VERSION 5.8 ;
BUSBITCHARS "[]" ;
DIVIDERCHAR "/" ;
UNITS
    DATABASE MICRONS 1000 ;
END UNITS

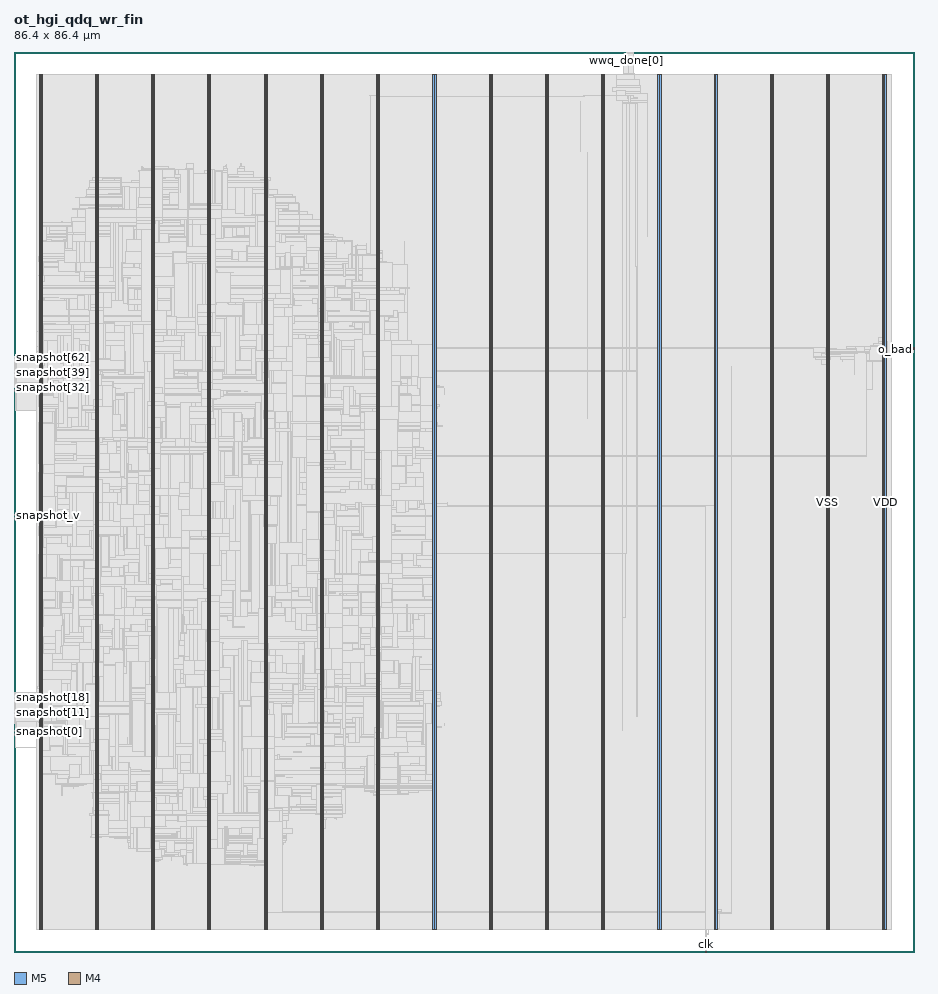
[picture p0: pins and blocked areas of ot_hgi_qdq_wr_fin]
MACRO ot_hgi_qdq_wr_fin
  FOREIGN ot_hgi_qdq_wr_fin 0 0 ;
  CLASS BLOCK ;
  SIZE 86.4 BY 86.4 ;
  PIN clk
    DIRECTION INPUT ;
    USE SIGNAL ;
    PORT
      LAYER M5 ;
        RECT  66.384 0 66.408 0.084 ;
    END
  END clk
  PIN o_bad
    DIRECTION OUTPUT ;
    USE SIGNAL ;
    PORT
      LAYER M4 ;
        RECT  86.316 57.84 86.4 57.864 ;
    END
  END o_bad
  PIN o_fin
    DIRECTION OUTPUT ;
    USE SIGNAL ;
    PORT
      LAYER M4 ;
        RECT  86.316 57.936 86.4 57.96 ;
    END
  END o_fin
  PIN o_idle
    DIRECTION OUTPUT ;
    USE SIGNAL ;
    PORT
      LAYER M4 ;
        RECT  86.316 58.032 86.4 58.056 ;
    END
  END o_idle
  PIN rst_n
    DIRECTION INPUT ;
    USE SIGNAL ;
    PORT
      LAYER M5 ;
        RECT  66.48 0 66.504 0.084 ;
    END
  END rst_n
  PIN snapshot[0]
    DIRECTION INPUT ;
    USE SIGNAL ;
    PORT
      LAYER M4 ;
        RECT  0 21.936 0.084 21.96 ;
    END
  END snapshot[0]
  PIN snapshot[10]
    DIRECTION INPUT ;
    USE SIGNAL ;
    PORT
      LAYER M4 ;
        RECT  0 22.896 0.084 22.92 ;
    END
  END snapshot[10]
  PIN snapshot[11]
    DIRECTION INPUT ;
    USE SIGNAL ;
    PORT
      LAYER M4 ;
        RECT  0 22.992 0.084 23.016 ;
    END
  END snapshot[11]
  PIN snapshot[12]
    DIRECTION INPUT ;
    USE SIGNAL ;
    PORT
      LAYER M4 ;
        RECT  0 23.088 0.084 23.112 ;
    END
  END snapshot[12]
  PIN snapshot[13]
    DIRECTION INPUT ;
    USE SIGNAL ;
    PORT
      LAYER M4 ;
        RECT  0 23.184 0.084 23.208 ;
    END
  END snapshot[13]
  PIN snapshot[14]
    DIRECTION INPUT ;
    USE SIGNAL ;
    PORT
      LAYER M4 ;
        RECT  0 23.28 0.084 23.304 ;
    END
  END snapshot[14]
  PIN snapshot[15]
    DIRECTION INPUT ;
    USE SIGNAL ;
    PORT
      LAYER M4 ;
        RECT  0 23.376 0.084 23.4 ;
    END
  END snapshot[15]
  PIN snapshot[16]
    DIRECTION INPUT ;
    USE SIGNAL ;
    PORT
      LAYER M4 ;
        RECT  0 23.472 0.084 23.496 ;
    END
  END snapshot[16]
  PIN snapshot[17]
    DIRECTION INPUT ;
    USE SIGNAL ;
    PORT
      LAYER M4 ;
        RECT  0 23.568 0.084 23.592 ;
    END
  END snapshot[17]
  PIN snapshot[18]
    DIRECTION INPUT ;
    USE SIGNAL ;
    PORT
      LAYER M4 ;
        RECT  0 23.664 0.084 23.688 ;
    END
  END snapshot[18]
  PIN snapshot[19]
    DIRECTION INPUT ;
    USE SIGNAL ;
    PORT
      LAYER M4 ;
        RECT  0 23.76 0.084 23.784 ;
    END
  END snapshot[19]
  PIN snapshot[1]
    DIRECTION INPUT ;
    USE SIGNAL ;
    PORT
      LAYER M4 ;
        RECT  0 22.032 0.084 22.056 ;
    END
  END snapshot[1]
  PIN snapshot[20]
    DIRECTION INPUT ;
    USE SIGNAL ;
    PORT
      LAYER M4 ;
        RECT  0 23.856 0.084 23.88 ;
    END
  END snapshot[20]
  PIN snapshot[21]
    DIRECTION INPUT ;
    USE SIGNAL ;
    PORT
      LAYER M4 ;
        RECT  0 23.952 0.084 23.976 ;
    END
  END snapshot[21]
  PIN snapshot[22]
    DIRECTION INPUT ;
    USE SIGNAL ;
    PORT
      LAYER M4 ;
        RECT  0 24.048 0.084 24.072 ;
    END
  END snapshot[22]
  PIN snapshot[23]
    DIRECTION INPUT ;
    USE SIGNAL ;
    PORT
      LAYER M4 ;
        RECT  0 24.144 0.084 24.168 ;
    END
  END snapshot[23]
  PIN snapshot[24]
    DIRECTION INPUT ;
    USE SIGNAL ;
    PORT
      LAYER M4 ;
        RECT  0 24.24 0.084 24.264 ;
    END
  END snapshot[24]
  PIN snapshot[25]
    DIRECTION INPUT ;
    USE SIGNAL ;
    PORT
      LAYER M4 ;
        RECT  0 24.336 0.084 24.36 ;
    END
  END snapshot[25]
  PIN snapshot[26]
    DIRECTION INPUT ;
    USE SIGNAL ;
    PORT
      LAYER M4 ;
        RECT  0 24.432 0.084 24.456 ;
    END
  END snapshot[26]
  PIN snapshot[27]
    DIRECTION INPUT ;
    USE SIGNAL ;
    PORT
      LAYER M4 ;
        RECT  0 24.528 0.084 24.552 ;
    END
  END snapshot[27]
  PIN snapshot[28]
    DIRECTION INPUT ;
    USE SIGNAL ;
    PORT
      LAYER M4 ;
        RECT  0 24.624 0.084 24.648 ;
    END
  END snapshot[28]
  PIN snapshot[29]
    DIRECTION INPUT ;
    USE SIGNAL ;
    PORT
      LAYER M4 ;
        RECT  0 24.72 0.084 24.744 ;
    END
  END snapshot[29]
  PIN snapshot[2]
    DIRECTION INPUT ;
    USE SIGNAL ;
    PORT
      LAYER M4 ;
        RECT  0 22.128 0.084 22.152 ;
    END
  END snapshot[2]
  PIN snapshot[30]
    DIRECTION INPUT ;
    USE SIGNAL ;
    PORT
      LAYER M4 ;
        RECT  0 24.816 0.084 24.84 ;
    END
  END snapshot[30]
  PIN snapshot[31]
    DIRECTION INPUT ;
    USE SIGNAL ;
    PORT
      LAYER M4 ;
        RECT  0 24.912 0.084 24.936 ;
    END
  END snapshot[31]
  PIN snapshot[32]
    DIRECTION INPUT ;
    USE SIGNAL ;
    PORT
      LAYER M4 ;
        RECT  0 54.192 0.084 54.216 ;
    END
  END snapshot[32]
  PIN snapshot[33]
    DIRECTION INPUT ;
    USE SIGNAL ;
    PORT
      LAYER M4 ;
        RECT  0 54.288 0.084 54.312 ;
    END
  END snapshot[33]
  PIN snapshot[34]
    DIRECTION INPUT ;
    USE SIGNAL ;
    PORT
      LAYER M4 ;
        RECT  0 54.384 0.084 54.408 ;
    END
  END snapshot[34]
  PIN snapshot[35]
    DIRECTION INPUT ;
    USE SIGNAL ;
    PORT
      LAYER M4 ;
        RECT  0 54.48 0.084 54.504 ;
    END
  END snapshot[35]
  PIN snapshot[36]
    DIRECTION INPUT ;
    USE SIGNAL ;
    PORT
      LAYER M4 ;
        RECT  0 54.576 0.084 54.6 ;
    END
  END snapshot[36]
  PIN snapshot[37]
    DIRECTION INPUT ;
    USE SIGNAL ;
    PORT
      LAYER M4 ;
        RECT  0 54.672 0.084 54.696 ;
    END
  END snapshot[37]
  PIN snapshot[38]
    DIRECTION INPUT ;
    USE SIGNAL ;
    PORT
      LAYER M4 ;
        RECT  0 54.768 0.084 54.792 ;
    END
  END snapshot[38]
  PIN snapshot[39]
    DIRECTION INPUT ;
    USE SIGNAL ;
    PORT
      LAYER M4 ;
        RECT  0 54.864 0.084 54.888 ;
    END
  END snapshot[39]
  PIN snapshot[3]
    DIRECTION INPUT ;
    USE SIGNAL ;
    PORT
      LAYER M4 ;
        RECT  0 22.224 0.084 22.248 ;
    END
  END snapshot[3]
  PIN snapshot[40]
    DIRECTION INPUT ;
    USE SIGNAL ;
    PORT
      LAYER M4 ;
        RECT  0 54.96 0.084 54.984 ;
    END
  END snapshot[40]
  PIN snapshot[41]
    DIRECTION INPUT ;
    USE SIGNAL ;
    PORT
      LAYER M4 ;
        RECT  0 55.056 0.084 55.08 ;
    END
  END snapshot[41]
  PIN snapshot[42]
    DIRECTION INPUT ;
    USE SIGNAL ;
    PORT
      LAYER M4 ;
        RECT  0 55.152 0.084 55.176 ;
    END
  END snapshot[42]
  PIN snapshot[43]
    DIRECTION INPUT ;
    USE SIGNAL ;
    PORT
      LAYER M4 ;
        RECT  0 55.248 0.084 55.272 ;
    END
  END snapshot[43]
  PIN snapshot[44]
    DIRECTION INPUT ;
    USE SIGNAL ;
    PORT
      LAYER M4 ;
        RECT  0 55.344 0.084 55.368 ;
    END
  END snapshot[44]
  PIN snapshot[45]
    DIRECTION INPUT ;
    USE SIGNAL ;
    PORT
      LAYER M4 ;
        RECT  0 55.44 0.084 55.464 ;
    END
  END snapshot[45]
  PIN snapshot[46]
    DIRECTION INPUT ;
    USE SIGNAL ;
    PORT
      LAYER M4 ;
        RECT  0 55.536 0.084 55.56 ;
    END
  END snapshot[46]
  PIN snapshot[47]
    DIRECTION INPUT ;
    USE SIGNAL ;
    PORT
      LAYER M4 ;
        RECT  0 55.632 0.084 55.656 ;
    END
  END snapshot[47]
  PIN snapshot[48]
    DIRECTION INPUT ;
    USE SIGNAL ;
    PORT
      LAYER M4 ;
        RECT  0 55.728 0.084 55.752 ;
    END
  END snapshot[48]
  PIN snapshot[49]
    DIRECTION INPUT ;
    USE SIGNAL ;
    PORT
      LAYER M4 ;
        RECT  0 55.824 0.084 55.848 ;
    END
  END snapshot[49]
  PIN snapshot[4]
    DIRECTION INPUT ;
    USE SIGNAL ;
    PORT
      LAYER M4 ;
        RECT  0 22.32 0.084 22.344 ;
    END
  END snapshot[4]
  PIN snapshot[50]
    DIRECTION INPUT ;
    USE SIGNAL ;
    PORT
      LAYER M4 ;
        RECT  0 55.92 0.084 55.944 ;
    END
  END snapshot[50]
  PIN snapshot[51]
    DIRECTION INPUT ;
    USE SIGNAL ;
    PORT
      LAYER M4 ;
        RECT  0 56.016 0.084 56.04 ;
    END
  END snapshot[51]
  PIN snapshot[52]
    DIRECTION INPUT ;
    USE SIGNAL ;
    PORT
      LAYER M4 ;
        RECT  0 56.112 0.084 56.136 ;
    END
  END snapshot[52]
  PIN snapshot[53]
    DIRECTION INPUT ;
    USE SIGNAL ;
    PORT
      LAYER M4 ;
        RECT  0 56.208 0.084 56.232 ;
    END
  END snapshot[53]
  PIN snapshot[54]
    DIRECTION INPUT ;
    USE SIGNAL ;
    PORT
      LAYER M4 ;
        RECT  0 56.304 0.084 56.328 ;
    END
  END snapshot[54]
  PIN snapshot[55]
    DIRECTION INPUT ;
    USE SIGNAL ;
    PORT
      LAYER M4 ;
        RECT  0 56.4 0.084 56.424 ;
    END
  END snapshot[55]
  PIN snapshot[56]
    DIRECTION INPUT ;
    USE SIGNAL ;
    PORT
      LAYER M4 ;
        RECT  0 56.496 0.084 56.52 ;
    END
  END snapshot[56]
  PIN snapshot[57]
    DIRECTION INPUT ;
    USE SIGNAL ;
    PORT
      LAYER M4 ;
        RECT  0 56.592 0.084 56.616 ;
    END
  END snapshot[57]
  PIN snapshot[58]
    DIRECTION INPUT ;
    USE SIGNAL ;
    PORT
      LAYER M4 ;
        RECT  0 56.688 0.084 56.712 ;
    END
  END snapshot[58]
  PIN snapshot[59]
    DIRECTION INPUT ;
    USE SIGNAL ;
    PORT
      LAYER M4 ;
        RECT  0 56.784 0.084 56.808 ;
    END
  END snapshot[59]
  PIN snapshot[5]
    DIRECTION INPUT ;
    USE SIGNAL ;
    PORT
      LAYER M4 ;
        RECT  0 22.416 0.084 22.44 ;
    END
  END snapshot[5]
  PIN snapshot[60]
    DIRECTION INPUT ;
    USE SIGNAL ;
    PORT
      LAYER M4 ;
        RECT  0 56.88 0.084 56.904 ;
    END
  END snapshot[60]
  PIN snapshot[61]
    DIRECTION INPUT ;
    USE SIGNAL ;
    PORT
      LAYER M4 ;
        RECT  0 56.976 0.084 57 ;
    END
  END snapshot[61]
  PIN snapshot[62]
    DIRECTION INPUT ;
    USE SIGNAL ;
    PORT
      LAYER M4 ;
        RECT  0 57.072 0.084 57.096 ;
    END
  END snapshot[62]
  PIN snapshot[63]
    DIRECTION INPUT ;
    USE SIGNAL ;
    PORT
      LAYER M4 ;
        RECT  0 57.168 0.084 57.192 ;
    END
  END snapshot[63]
  PIN snapshot[6]
    DIRECTION INPUT ;
    USE SIGNAL ;
    PORT
      LAYER M4 ;
        RECT  0 22.512 0.084 22.536 ;
    END
  END snapshot[6]
  PIN snapshot[7]
    DIRECTION INPUT ;
    USE SIGNAL ;
    PORT
      LAYER M4 ;
        RECT  0 22.608 0.084 22.632 ;
    END
  END snapshot[7]
  PIN snapshot[8]
    DIRECTION INPUT ;
    USE SIGNAL ;
    PORT
      LAYER M4 ;
        RECT  0 22.704 0.084 22.728 ;
    END
  END snapshot[8]
  PIN snapshot[9]
    DIRECTION INPUT ;
    USE SIGNAL ;
    PORT
      LAYER M4 ;
        RECT  0 22.8 0.084 22.824 ;
    END
  END snapshot[9]
  PIN snapshot_v
    DIRECTION INPUT ;
    USE SIGNAL ;
    PORT
      LAYER M4 ;
        RECT  0 41.904 0.084 41.928 ;
    END
    PORT
      LAYER M4 ;
        RECT  0.06 41.904 2.408 41.928 ;
    END
  END snapshot_v
  PIN wwq_done[0]
    DIRECTION INPUT ;
    USE SIGNAL ;
    PORT
      LAYER M5 ;
        RECT  58.8 86.316 58.824 86.4 ;
    END
  END wwq_done[0]
  PIN wwq_done[1]
    DIRECTION INPUT ;
    USE SIGNAL ;
    PORT
      LAYER M5 ;
        RECT  58.896 86.316 58.92 86.4 ;
    END
  END wwq_done[1]
  PIN wwq_done[2]
    DIRECTION INPUT ;
    USE SIGNAL ;
    PORT
      LAYER M5 ;
        RECT  58.992 86.316 59.016 86.4 ;
    END
  END wwq_done[2]
  PIN wwq_done[3]
    DIRECTION INPUT ;
    USE SIGNAL ;
    PORT
      LAYER M5 ;
        RECT  59.088 86.316 59.112 86.4 ;
    END
  END wwq_done[3]
  PIN wwq_done[4]
    DIRECTION INPUT ;
    USE SIGNAL ;
    PORT
      LAYER M5 ;
        RECT  59.184 86.316 59.208 86.4 ;
    END
  END wwq_done[4]
  PIN wwq_done[5]
    DIRECTION INPUT ;
    USE SIGNAL ;
    PORT
      LAYER M5 ;
        RECT  59.28 86.316 59.304 86.4 ;
    END
  END wwq_done[5]
  PIN wwq_done[6]
    DIRECTION INPUT ;
    USE SIGNAL ;
    PORT
      LAYER M5 ;
        RECT  59.376 86.316 59.4 86.4 ;
    END
  END wwq_done[6]
  PIN wwq_done[7]
    DIRECTION INPUT ;
    USE SIGNAL ;
    PORT
      LAYER M5 ;
        RECT  59.472 86.316 59.496 86.4 ;
    END
  END wwq_done[7]
  PIN VDD
    DIRECTION INOUT ;
    USE POWER ;
    PORT
      LAYER M5 ;
        RECT  83.592 2.151 83.712 84.249 ;
        RECT  78.192 2.151 78.312 84.249 ;
        RECT  72.792 2.151 72.912 84.249 ;
        RECT  67.392 2.151 67.512 84.249 ;
        RECT  61.992 2.151 62.112 84.249 ;
        RECT  56.592 2.151 56.712 84.249 ;
        RECT  51.192 2.151 51.312 84.249 ;
        RECT  45.792 2.151 45.912 84.249 ;
        RECT  40.392 2.151 40.512 84.249 ;
        RECT  34.992 2.151 35.112 84.249 ;
        RECT  29.592 2.151 29.712 84.249 ;
        RECT  24.192 2.151 24.312 84.249 ;
        RECT  18.792 2.151 18.912 84.249 ;
        RECT  13.392 2.151 13.512 84.249 ;
        RECT  7.992 2.151 8.112 84.249 ;
        RECT  2.592 2.151 2.712 84.249 ;
    END
  END VDD
  PIN VSS
    DIRECTION INOUT ;
    USE GROUND ;
    PORT
      LAYER M5 ;
        RECT  83.4 2.137 83.52 84.263 ;
        RECT  78 2.137 78.12 84.263 ;
        RECT  72.6 2.137 72.72 84.263 ;
        RECT  67.2 2.137 67.32 84.263 ;
        RECT  61.8 2.137 61.92 84.263 ;
        RECT  56.4 2.137 56.52 84.263 ;
        RECT  51 2.137 51.12 84.263 ;
        RECT  45.6 2.137 45.72 84.263 ;
        RECT  40.2 2.137 40.32 84.263 ;
        RECT  34.8 2.137 34.92 84.263 ;
        RECT  29.4 2.137 29.52 84.263 ;
        RECT  24 2.137 24.12 84.263 ;
        RECT  18.6 2.137 18.72 84.263 ;
        RECT  13.2 2.137 13.32 84.263 ;
        RECT  7.8 2.137 7.92 84.263 ;
        RECT  2.4 2.137 2.52 84.263 ;
    END
  END VSS
  # OT_OBS_CLOSED layer=M5 d_um=1.536 added=257
  OBS
    LAYER RVTN ;
     RECT  2.16 2.16 84.24 2.295 ;
     RECT  2.16 2.565 84.24 2.835 ;
     RECT  2.16 3.105 84.24 3.375 ;
     RECT  2.16 3.645 84.24 3.915 ;
     RECT  2.16 4.185 84.24 4.455 ;
     RECT  2.16 4.725 84.24 4.995 ;
     RECT  2.16 5.265 84.24 5.535 ;
     RECT  2.16 5.805 84.24 6.075 ;
     RECT  2.16 6.345 84.24 6.615 ;
     RECT  2.16 6.885 84.24 7.155 ;
     RECT  2.16 7.425 84.24 7.695 ;
     RECT  2.16 7.965 84.24 8.235 ;
     RECT  2.16 8.505 84.24 8.775 ;
     RECT  2.16 9.045 84.24 9.315 ;
     RECT  2.16 9.585 84.24 9.855 ;
     RECT  2.16 10.125 84.24 10.395 ;
     RECT  2.16 10.665 84.24 10.935 ;
     RECT  2.16 11.205 84.24 11.475 ;
     RECT  2.16 11.745 84.24 12.015 ;
     RECT  2.16 12.285 84.24 12.555 ;
     RECT  2.16 12.825 84.24 13.095 ;
     RECT  2.16 13.365 84.24 13.635 ;
     RECT  2.16 13.905 84.24 14.175 ;
     RECT  2.16 14.445 84.24 14.715 ;
     RECT  2.16 14.985 84.24 15.255 ;
     RECT  2.16 15.525 84.24 15.795 ;
     RECT  2.16 16.065 84.24 16.335 ;
     RECT  2.16 16.605 84.24 16.875 ;
     RECT  2.16 17.145 84.24 17.415 ;
     RECT  2.16 17.685 84.24 17.955 ;
     RECT  2.16 18.225 84.24 18.495 ;
     RECT  2.16 18.765 84.24 19.035 ;
     RECT  2.16 19.305 84.24 19.575 ;
     RECT  2.16 19.845 84.24 20.115 ;
     RECT  2.16 20.385 84.24 20.655 ;
     RECT  2.16 20.925 84.24 21.195 ;
     RECT  2.16 21.465 84.24 21.735 ;
     RECT  2.16 22.005 84.24 22.275 ;
     RECT  2.16 22.545 84.24 22.815 ;
     RECT  2.16 23.085 84.24 23.355 ;
     RECT  2.16 23.625 84.24 23.895 ;
     RECT  2.16 24.165 84.24 24.435 ;
     RECT  2.16 24.705 84.24 24.975 ;
     RECT  2.16 25.245 84.24 25.515 ;
     RECT  2.16 25.785 84.24 26.055 ;
     RECT  2.16 26.325 84.24 26.595 ;
     RECT  2.16 26.865 84.24 27.135 ;
     RECT  2.16 27.405 84.24 27.675 ;
     RECT  2.16 27.945 84.24 28.215 ;
     RECT  2.16 28.485 84.24 28.755 ;
     RECT  2.16 29.025 84.24 29.295 ;
     RECT  2.16 29.565 84.24 29.835 ;
     RECT  2.16 30.105 84.24 30.375 ;
     RECT  2.16 30.645 84.24 30.915 ;
     RECT  2.16 31.185 84.24 31.455 ;
     RECT  2.16 31.725 84.24 31.995 ;
     RECT  2.16 32.265 84.24 32.535 ;
     RECT  2.16 32.805 84.24 33.075 ;
     RECT  2.16 33.345 84.24 33.615 ;
     RECT  2.16 33.885 84.24 34.155 ;
     RECT  2.16 34.425 84.24 34.695 ;
     RECT  2.16 34.965 84.24 35.235 ;
     RECT  2.16 35.505 84.24 35.775 ;
     RECT  2.16 36.045 84.24 36.315 ;
     RECT  2.16 36.585 84.24 36.855 ;
     RECT  2.16 37.125 84.24 37.395 ;
     RECT  2.16 37.665 84.24 37.935 ;
     RECT  2.16 38.205 84.24 38.475 ;
     RECT  2.16 38.745 84.24 39.015 ;
     RECT  2.16 39.285 84.24 39.555 ;
     RECT  2.16 39.825 84.24 40.095 ;
     RECT  2.16 40.365 84.24 40.635 ;
     RECT  2.16 40.905 84.24 41.175 ;
     RECT  2.16 41.445 84.24 41.715 ;
     RECT  2.16 41.985 84.24 42.255 ;
     RECT  2.16 42.525 84.24 42.795 ;
     RECT  2.16 43.065 84.24 43.335 ;
     RECT  2.16 43.605 84.24 43.875 ;
     RECT  2.16 44.145 84.24 44.415 ;
     RECT  2.16 44.685 84.24 44.955 ;
     RECT  2.16 45.225 84.24 45.495 ;
     RECT  2.16 45.765 84.24 46.035 ;
     RECT  2.16 46.305 84.24 46.575 ;
     RECT  2.16 46.845 84.24 47.115 ;
     RECT  2.16 47.385 84.24 47.655 ;
     RECT  2.16 47.925 84.24 48.195 ;
     RECT  2.16 48.465 84.24 48.735 ;
     RECT  2.16 49.005 84.24 49.275 ;
     RECT  2.16 49.545 84.24 49.815 ;
     RECT  2.16 50.085 84.24 50.355 ;
     RECT  2.16 50.625 84.24 50.895 ;
     RECT  2.16 51.165 84.24 51.435 ;
     RECT  2.16 51.705 84.24 51.975 ;
     RECT  2.16 52.245 84.24 52.515 ;
     RECT  2.16 52.785 84.24 53.055 ;
     RECT  2.16 53.325 84.24 53.595 ;
     RECT  2.16 53.865 84.24 54.135 ;
     RECT  2.16 54.405 84.24 54.675 ;
     RECT  2.16 54.945 84.24 55.215 ;
     RECT  2.16 55.485 84.24 55.755 ;
     RECT  2.16 56.025 84.24 56.295 ;
     RECT  2.16 56.565 84.24 56.835 ;
     RECT  2.16 57.105 84.24 57.375 ;
     RECT  2.16 57.645 84.24 57.915 ;
     RECT  2.16 58.185 84.24 58.455 ;
     RECT  2.16 58.725 84.24 58.995 ;
     RECT  2.16 59.265 84.24 59.535 ;
     RECT  2.16 59.805 84.24 60.075 ;
     RECT  2.16 60.345 84.24 60.615 ;
     RECT  2.16 60.885 84.24 61.155 ;
     RECT  2.16 61.425 84.24 61.695 ;
     RECT  2.16 61.965 84.24 62.235 ;
     RECT  2.16 62.505 84.24 62.775 ;
     RECT  2.16 63.045 84.24 63.315 ;
     RECT  2.16 63.585 84.24 63.855 ;
     RECT  2.16 64.125 84.24 64.395 ;
     RECT  2.16 64.665 84.24 64.935 ;
     RECT  2.16 65.205 84.24 65.475 ;
     RECT  2.16 65.745 84.24 66.015 ;
     RECT  2.16 66.285 84.24 66.555 ;
     RECT  2.16 66.825 84.24 67.095 ;
     RECT  2.16 67.365 84.24 67.635 ;
     RECT  2.16 67.905 84.24 68.175 ;
     RECT  2.16 68.445 84.24 68.715 ;
     RECT  2.16 68.985 84.24 69.255 ;
     RECT  2.16 69.525 84.24 69.795 ;
     RECT  2.16 70.065 84.24 70.335 ;
     RECT  2.16 70.605 84.24 70.875 ;
     RECT  2.16 71.145 84.24 71.415 ;
     RECT  2.16 71.685 84.24 71.955 ;
     RECT  2.16 72.225 84.24 72.495 ;
     RECT  2.16 72.765 84.24 73.035 ;
     RECT  2.16 73.305 84.24 73.575 ;
     RECT  2.16 73.845 84.24 74.115 ;
     RECT  2.16 74.385 84.24 74.655 ;
     RECT  2.16 74.925 84.24 75.195 ;
     RECT  2.16 75.465 84.24 75.735 ;
     RECT  2.16 76.005 84.24 76.275 ;
     RECT  2.16 76.545 84.24 76.815 ;
     RECT  2.16 77.085 84.24 77.355 ;
     RECT  2.16 77.625 84.24 77.895 ;
     RECT  2.16 78.165 84.24 78.435 ;
     RECT  2.16 78.705 84.24 78.975 ;
     RECT  2.16 79.245 84.24 79.515 ;
     RECT  2.16 79.785 84.24 80.055 ;
     RECT  2.16 80.325 84.24 80.595 ;
     RECT  2.16 80.865 84.24 81.135 ;
     RECT  2.16 81.405 84.24 81.675 ;
     RECT  2.16 81.945 84.24 82.215 ;
     RECT  2.16 82.485 84.24 82.755 ;
     RECT  2.16 83.025 84.24 83.295 ;
     RECT  2.16 83.565 84.24 83.835 ;
     RECT  2.16 84.105 84.24 84.24 ;
    LAYER RVTP ;
     RECT  2.16 2.295 84.24 2.565 ;
     RECT  2.16 2.835 84.24 3.105 ;
     RECT  2.16 3.375 84.24 3.645 ;
     RECT  2.16 3.915 84.24 4.185 ;
     RECT  2.16 4.455 84.24 4.725 ;
     RECT  2.16 4.995 84.24 5.265 ;
     RECT  2.16 5.535 84.24 5.805 ;
     RECT  2.16 6.075 84.24 6.345 ;
     RECT  2.16 6.615 84.24 6.885 ;
     RECT  2.16 7.155 84.24 7.425 ;
     RECT  2.16 7.695 84.24 7.965 ;
     RECT  2.16 8.235 84.24 8.505 ;
     RECT  2.16 8.775 84.24 9.045 ;
     RECT  2.16 9.315 84.24 9.585 ;
     RECT  2.16 9.855 84.24 10.125 ;
     RECT  2.16 10.395 84.24 10.665 ;
     RECT  2.16 10.935 84.24 11.205 ;
     RECT  2.16 11.475 84.24 11.745 ;
     RECT  2.16 12.015 84.24 12.285 ;
     RECT  2.16 12.555 84.24 12.825 ;
     RECT  2.16 13.095 84.24 13.365 ;
     RECT  2.16 13.635 84.24 13.905 ;
     RECT  2.16 14.175 84.24 14.445 ;
     RECT  2.16 14.715 84.24 14.985 ;
     RECT  2.16 15.255 84.24 15.525 ;
     RECT  2.16 15.795 84.24 16.065 ;
     RECT  2.16 16.335 84.24 16.605 ;
     RECT  2.16 16.875 84.24 17.145 ;
     RECT  2.16 17.415 84.24 17.685 ;
     RECT  2.16 17.955 84.24 18.225 ;
     RECT  2.16 18.495 84.24 18.765 ;
     RECT  2.16 19.035 84.24 19.305 ;
     RECT  2.16 19.575 84.24 19.845 ;
     RECT  2.16 20.115 84.24 20.385 ;
     RECT  2.16 20.655 84.24 20.925 ;
     RECT  2.16 21.195 84.24 21.465 ;
     RECT  2.16 21.735 84.24 22.005 ;
     RECT  2.16 22.275 84.24 22.545 ;
     RECT  2.16 22.815 84.24 23.085 ;
     RECT  2.16 23.355 84.24 23.625 ;
     RECT  2.16 23.895 84.24 24.165 ;
     RECT  2.16 24.435 84.24 24.705 ;
     RECT  2.16 24.975 84.24 25.245 ;
     RECT  2.16 25.515 84.24 25.785 ;
     RECT  2.16 26.055 84.24 26.325 ;
     RECT  2.16 26.595 84.24 26.865 ;
     RECT  2.16 27.135 84.24 27.405 ;
     RECT  2.16 27.675 84.24 27.945 ;
     RECT  2.16 28.215 84.24 28.485 ;
     RECT  2.16 28.755 84.24 29.025 ;
     RECT  2.16 29.295 84.24 29.565 ;
     RECT  2.16 29.835 84.24 30.105 ;
     RECT  2.16 30.375 84.24 30.645 ;
     RECT  2.16 30.915 84.24 31.185 ;
     RECT  2.16 31.455 84.24 31.725 ;
     RECT  2.16 31.995 84.24 32.265 ;
     RECT  2.16 32.535 84.24 32.805 ;
     RECT  2.16 33.075 84.24 33.345 ;
     RECT  2.16 33.615 84.24 33.885 ;
     RECT  2.16 34.155 84.24 34.425 ;
     RECT  2.16 34.695 84.24 34.965 ;
     RECT  2.16 35.235 84.24 35.505 ;
     RECT  2.16 35.775 84.24 36.045 ;
     RECT  2.16 36.315 84.24 36.585 ;
     RECT  2.16 36.855 84.24 37.125 ;
     RECT  2.16 37.395 84.24 37.665 ;
     RECT  2.16 37.935 84.24 38.205 ;
     RECT  2.16 38.475 84.24 38.745 ;
     RECT  2.16 39.015 84.24 39.285 ;
     RECT  2.16 39.555 84.24 39.825 ;
     RECT  2.16 40.095 84.24 40.365 ;
     RECT  2.16 40.635 84.24 40.905 ;
     RECT  2.16 41.175 84.24 41.445 ;
     RECT  2.16 41.715 84.24 41.985 ;
     RECT  2.16 42.255 84.24 42.525 ;
     RECT  2.16 42.795 84.24 43.065 ;
     RECT  2.16 43.335 84.24 43.605 ;
     RECT  2.16 43.875 84.24 44.145 ;
     RECT  2.16 44.415 84.24 44.685 ;
     RECT  2.16 44.955 84.24 45.225 ;
     RECT  2.16 45.495 84.24 45.765 ;
     RECT  2.16 46.035 84.24 46.305 ;
     RECT  2.16 46.575 84.24 46.845 ;
     RECT  2.16 47.115 84.24 47.385 ;
     RECT  2.16 47.655 84.24 47.925 ;
     RECT  2.16 48.195 84.24 48.465 ;
     RECT  2.16 48.735 84.24 49.005 ;
     RECT  2.16 49.275 84.24 49.545 ;
     RECT  2.16 49.815 84.24 50.085 ;
     RECT  2.16 50.355 84.24 50.625 ;
     RECT  2.16 50.895 84.24 51.165 ;
     RECT  2.16 51.435 84.24 51.705 ;
     RECT  2.16 51.975 84.24 52.245 ;
     RECT  2.16 52.515 84.24 52.785 ;
     RECT  2.16 53.055 84.24 53.325 ;
     RECT  2.16 53.595 84.24 53.865 ;
     RECT  2.16 54.135 84.24 54.405 ;
     RECT  2.16 54.675 84.24 54.945 ;
     RECT  2.16 55.215 84.24 55.485 ;
     RECT  2.16 55.755 84.24 56.025 ;
     RECT  2.16 56.295 84.24 56.565 ;
     RECT  2.16 56.835 84.24 57.105 ;
     RECT  2.16 57.375 84.24 57.645 ;
     RECT  2.16 57.915 84.24 58.185 ;
     RECT  2.16 58.455 84.24 58.725 ;
     RECT  2.16 58.995 84.24 59.265 ;
     RECT  2.16 59.535 84.24 59.805 ;
     RECT  2.16 60.075 84.24 60.345 ;
     RECT  2.16 60.615 84.24 60.885 ;
     RECT  2.16 61.155 84.24 61.425 ;
     RECT  2.16 61.695 84.24 61.965 ;
     RECT  2.16 62.235 84.24 62.505 ;
     RECT  2.16 62.775 84.24 63.045 ;
     RECT  2.16 63.315 84.24 63.585 ;
     RECT  2.16 63.855 84.24 64.125 ;
     RECT  2.16 64.395 84.24 64.665 ;
     RECT  2.16 64.935 84.24 65.205 ;
     RECT  2.16 65.475 84.24 65.745 ;
     RECT  2.16 66.015 84.24 66.285 ;
     RECT  2.16 66.555 84.24 66.825 ;
     RECT  2.16 67.095 84.24 67.365 ;
     RECT  2.16 67.635 84.24 67.905 ;
     RECT  2.16 68.175 84.24 68.445 ;
     RECT  2.16 68.715 84.24 68.985 ;
     RECT  2.16 69.255 84.24 69.525 ;
     RECT  2.16 69.795 84.24 70.065 ;
     RECT  2.16 70.335 84.24 70.605 ;
     RECT  2.16 70.875 84.24 71.145 ;
     RECT  2.16 71.415 84.24 71.685 ;
     RECT  2.16 71.955 84.24 72.225 ;
     RECT  2.16 72.495 84.24 72.765 ;
     RECT  2.16 73.035 84.24 73.305 ;
     RECT  2.16 73.575 84.24 73.845 ;
     RECT  2.16 74.115 84.24 74.385 ;
     RECT  2.16 74.655 84.24 74.925 ;
     RECT  2.16 75.195 84.24 75.465 ;
     RECT  2.16 75.735 84.24 76.005 ;
     RECT  2.16 76.275 84.24 76.545 ;
     RECT  2.16 76.815 84.24 77.085 ;
     RECT  2.16 77.355 84.24 77.625 ;
     RECT  2.16 77.895 84.24 78.165 ;
     RECT  2.16 78.435 84.24 78.705 ;
     RECT  2.16 78.975 84.24 79.245 ;
     RECT  2.16 79.515 84.24 79.785 ;
     RECT  2.16 80.055 84.24 80.325 ;
     RECT  2.16 80.595 84.24 80.865 ;
     RECT  2.16 81.135 84.24 81.405 ;
     RECT  2.16 81.675 84.24 81.945 ;
     RECT  2.16 82.215 84.24 82.485 ;
     RECT  2.16 82.755 84.24 83.025 ;
     RECT  2.16 83.295 84.24 83.565 ;
     RECT  2.16 83.835 84.24 84.105 ;
    LAYER M1 ;
     RECT  2.16 2.151 84.24 84.249 ;
    LAYER M2 ;
     RECT  0.103 21.24 0.175 21.258 ;
     RECT  0.103 22.212 0.175 22.608 ;
     RECT  0.103 52.02 0.211 52.038 ;
     RECT  0.139 52.794 0.211 52.812 ;
     RECT  0.211 52.02 0.247 52.812 ;
     RECT  0.175 53.568 0.247 53.586 ;
     RECT  0.247 52.02 0.283 53.586 ;
     RECT  0.103 54.45 0.283 54.468 ;
     RECT  0.139 19.62 2.16 19.638 ;
     RECT  0.175 21.24 2.16 22.608 ;
     RECT  0.103 23.832 2.16 23.85 ;
     RECT  2.119 25.254 2.16 25.272 ;
     RECT  0.283 52.02 2.16 54.468 ;
     RECT  0.103 55.8 2.16 55.818 ;
     RECT  2.16 2.151 84.24 84.249 ;
     RECT  84.24 57.546 85.487 58.104 ;
     RECT  85.487 57.546 86.315 57.564 ;
    LAYER M3 ;
     RECT  66.672 1.723 66.69 2.143 ;
     RECT  66.672 2.143 67.305 2.255 ;
     RECT  67.215 2.255 67.305 2.263 ;
     RECT  2.415 2.143 2.505 2.413 ;
     RECT  7.815 2.143 7.905 2.413 ;
     RECT  13.215 2.143 13.305 2.413 ;
     RECT  18.615 2.143 18.705 2.413 ;
     RECT  24.015 2.143 24.105 2.413 ;
     RECT  29.415 2.143 29.505 2.413 ;
     RECT  34.815 2.143 34.905 2.413 ;
     RECT  40.215 2.143 40.305 2.413 ;
     RECT  45.615 2.143 45.705 2.413 ;
     RECT  51.015 2.143 51.105 2.413 ;
     RECT  56.415 2.143 56.505 2.413 ;
     RECT  61.815 2.143 61.905 2.413 ;
     RECT  72.615 2.143 72.705 2.413 ;
     RECT  78.015 2.143 78.105 2.413 ;
     RECT  83.415 2.143 83.505 2.413 ;
     RECT  67.215 2.263 67.698 3.721 ;
     RECT  67.215 3.721 68.886 3.839 ;
     RECT  67.215 3.839 67.95 4.109 ;
     RECT  16.56 8.275 16.578 8.311 ;
     RECT  23.076 8.203 23.094 8.311 ;
     RECT  24.015 2.413 24.297 8.311 ;
     RECT  22.644 8.311 24.297 8.401 ;
     RECT  16.56 8.311 16.65 8.437 ;
     RECT  22.14 8.401 24.297 8.437 ;
     RECT  18.615 2.413 18.897 8.539 ;
     RECT  20.016 8.437 20.034 8.545 ;
     RECT  16.236 8.437 16.65 8.581 ;
     RECT  17.46 8.491 17.478 8.581 ;
     RECT  18.54 8.539 18.897 8.581 ;
     RECT  19.656 8.545 20.034 8.581 ;
     RECT  21.744 8.437 24.297 8.581 ;
     RECT  13.215 2.413 13.497 8.671 ;
     RECT  16.236 8.581 18.897 8.671 ;
     RECT  19.656 8.581 24.297 8.671 ;
     RECT  13.215 8.671 13.842 8.743 ;
     RECT  13.215 8.743 13.914 8.815 ;
     RECT  13.215 8.815 14.094 8.851 ;
     RECT  16.236 8.671 24.297 8.851 ;
     RECT  16.236 8.851 24.354 9.067 ;
     RECT  13.215 8.851 14.274 9.121 ;
     RECT  15.084 8.815 15.102 9.121 ;
     RECT  16.164 9.067 24.354 9.121 ;
     RECT  13.215 9.121 24.354 9.283 ;
     RECT  13.215 9.283 24.714 9.319 ;
     RECT  13.215 9.319 24.858 9.391 ;
     RECT  13.215 9.391 24.966 9.509 ;
     RECT  15.408 9.509 24.966 9.545 ;
     RECT  11.844 9.625 11.862 9.661 ;
     RECT  13.215 9.509 14.634 9.661 ;
     RECT  11.844 9.661 14.634 9.779 ;
     RECT  15.408 9.545 24.894 9.779 ;
     RECT  11.016 9.925 11.034 9.931 ;
     RECT  11.844 9.779 14.598 9.931 ;
     RECT  11.016 9.931 14.598 10.129 ;
     RECT  15.444 9.779 24.894 10.435 ;
     RECT  25.812 10.363 25.83 10.435 ;
     RECT  10.98 10.129 14.598 10.471 ;
     RECT  15.444 10.435 25.83 10.471 ;
     RECT  10.908 10.471 14.598 10.705 ;
     RECT  15.444 10.471 26.082 10.705 ;
     RECT  10.908 10.705 26.19 10.867 ;
     RECT  10.188 10.867 26.19 10.903 ;
     RECT  7.815 2.413 8.097 11.011 ;
     RECT  9.648 10.903 26.19 11.011 ;
     RECT  7.776 11.011 8.37 11.101 ;
     RECT  9.144 11.011 26.19 11.101 ;
     RECT  7.776 11.101 26.19 11.165 ;
     RECT  7.815 11.165 26.19 11.407 ;
     RECT  29.415 2.413 29.697 11.821 ;
     RECT  7.815 11.407 26.766 11.849 ;
     RECT  7.815 11.849 26.118 12.631 ;
     RECT  29.415 11.821 29.862 12.757 ;
     RECT  30.924 12.757 30.942 12.793 ;
     RECT  29.415 12.757 30.006 12.901 ;
     RECT  30.78 12.793 30.942 12.901 ;
     RECT  7.815 12.631 26.37 13.099 ;
     RECT  29.415 12.901 31.554 13.171 ;
     RECT  7.236 13.099 26.37 13.289 ;
     RECT  28.116 13.297 28.134 13.333 ;
     RECT  28.944 13.171 31.554 13.333 ;
     RECT  7.488 13.289 26.37 13.441 ;
     RECT  28.116 13.333 31.554 13.567 ;
     RECT  27.936 13.567 31.554 13.711 ;
     RECT  7.488 13.441 26.658 13.837 ;
     RECT  27.504 13.711 31.554 13.837 ;
     RECT  7.488 13.837 31.554 13.865 ;
     RECT  7.776 13.865 31.554 13.949 ;
     RECT  27.144 13.949 31.554 14.135 ;
     RECT  7.776 13.949 26.046 14.405 ;
     RECT  7.776 14.405 15.57 14.755 ;
     RECT  16.308 14.405 26.046 14.881 ;
     RECT  16.308 14.881 26.55 14.971 ;
     RECT  27.468 14.135 31.482 14.971 ;
     RECT  34.815 2.413 35.097 14.989 ;
     RECT  34.524 14.989 35.097 15.163 ;
     RECT  7.488 14.755 15.57 15.259 ;
     RECT  16.308 14.971 31.482 15.259 ;
     RECT  34.524 15.163 35.262 15.331 ;
     RECT  36.504 15.151 36.522 15.331 ;
     RECT  37.836 15.163 37.854 15.331 ;
     RECT  7.488 15.259 31.482 15.341 ;
     RECT  34.236 15.331 37.098 15.421 ;
     RECT  37.836 15.331 38.79 15.457 ;
     RECT  37.836 15.457 39.258 15.493 ;
     RECT  40.215 2.413 40.497 15.493 ;
     RECT  33.66 15.421 37.098 15.529 ;
     RECT  37.836 15.493 40.497 15.529 ;
     RECT  7.815 15.341 31.482 15.565 ;
     RECT  33.66 15.529 40.497 15.727 ;
     RECT  33.624 15.727 40.497 15.832 ;
     RECT  4.608 15.025 4.626 15.871 ;
     RECT  5.688 15.691 5.706 15.871 ;
     RECT  32.976 15.832 40.497 15.871 ;
     RECT  32.616 15.871 40.497 15.961 ;
     RECT  4.608 15.871 6.174 15.997 ;
     RECT  7.815 15.565 31.77 15.997 ;
     RECT  32.508 15.961 40.497 15.997 ;
     RECT  4.608 15.997 6.642 16.069 ;
     RECT  3.996 16.069 6.642 16.105 ;
     RECT  3.996 16.105 7.002 16.141 ;
     RECT  7.815 15.997 40.497 16.141 ;
     RECT  3.996 16.141 40.497 17.083 ;
     RECT  3.564 17.083 40.497 17.419 ;
     RECT  2.415 2.413 2.697 18.769 ;
     RECT  3.456 17.419 40.497 18.769 ;
     RECT  2.415 18.769 40.497 19.769 ;
     RECT  23.868 19.769 40.497 20.587 ;
     RECT  2.415 19.769 23.13 20.683 ;
     RECT  23.868 20.587 40.554 20.683 ;
     RECT  2.415 20.683 40.554 20.731 ;
     RECT  2.376 20.731 40.554 20.993 ;
     RECT  0.144 19.615 0.162 21.235 ;
     RECT  0.108 21.235 0.162 21.505 ;
     RECT  2.415 20.993 40.554 21.505 ;
     RECT  2.415 21.505 41.058 21.659 ;
     RECT  2.415 21.659 40.59 21.695 ;
     RECT  2.415 21.695 40.554 21.929 ;
     RECT  41.328 21.739 41.346 21.929 ;
     RECT  2.415 21.929 40.497 22.045 ;
     RECT  0.108 21.505 0.234 22.315 ;
     RECT  2.304 22.045 40.497 22.891 ;
     RECT  0.108 22.315 0.342 23.021 ;
     RECT  0.144 23.021 0.342 23.309 ;
     RECT  2.304 22.891 40.59 23.593 ;
     RECT  2.304 23.593 40.878 23.701 ;
     RECT  0.144 23.309 0.162 23.827 ;
     RECT  0.108 23.827 0.162 24.077 ;
     RECT  2.304 23.701 41.058 24.089 ;
     RECT  2.304 24.089 40.914 24.331 ;
     RECT  0.18 24.139 0.342 24.653 ;
     RECT  2.268 24.331 40.914 24.715 ;
     RECT  0.18 24.653 0.198 24.797 ;
     RECT  2.124 24.715 40.914 24.935 ;
     RECT  2.124 24.935 40.497 25.277 ;
     RECT  2.268 25.277 40.497 25.475 ;
     RECT  2.304 25.475 40.497 25.745 ;
     RECT  2.34 25.745 40.497 26.285 ;
     RECT  2.376 26.285 40.497 27.031 ;
     RECT  2.34 27.031 40.497 27.643 ;
     RECT  2.304 27.643 40.497 29.057 ;
     RECT  2.376 29.057 40.497 30.137 ;
     RECT  2.376 30.137 39.438 30.299 ;
     RECT  58.428 21.235 58.446 32.071 ;
     RECT  2.376 30.299 39.402 32.297 ;
     RECT  12.312 32.297 39.402 32.539 ;
     RECT  40.215 30.137 40.497 32.539 ;
     RECT  2.376 32.297 11.43 33.115 ;
     RECT  12.312 32.539 40.497 33.115 ;
     RECT  2.376 33.115 40.497 33.781 ;
     RECT  2.304 33.781 40.497 33.809 ;
     RECT  2.304 33.809 39.402 34.627 ;
     RECT  40.215 33.809 40.497 34.627 ;
     RECT  2.304 34.627 40.497 35.303 ;
     RECT  2.304 35.303 10.746 36.041 ;
     RECT  10.08 36.041 10.746 36.121 ;
     RECT  11.556 35.303 40.497 36.121 ;
     RECT  2.304 36.041 9.342 36.509 ;
     RECT  2.34 36.509 9.342 36.895 ;
     RECT  10.08 36.121 40.497 36.895 ;
     RECT  2.34 36.895 40.497 37.661 ;
     RECT  2.376 37.661 40.497 38.189 ;
     RECT  58.428 32.071 58.662 38.251 ;
     RECT  2.415 38.189 40.497 39.623 ;
     RECT  2.415 39.623 39.474 40.021 ;
     RECT  2.34 40.021 39.474 40.061 ;
     RECT  2.376 40.061 39.474 40.829 ;
     RECT  2.415 40.829 39.474 41.791 ;
     RECT  40.215 39.623 40.497 41.791 ;
     RECT  2.415 41.791 40.497 41.899 ;
     RECT  2.304 41.899 40.497 41.909 ;
     RECT  2.304 41.909 39.474 41.945 ;
     RECT  2.376 41.945 39.474 42.485 ;
     RECT  2.376 42.485 39.402 42.989 ;
     RECT  41.292 42.811 41.31 42.989 ;
     RECT  41.58 43.051 41.598 43.169 ;
     RECT  2.376 42.989 39.294 44.681 ;
     RECT  2.376 44.681 38.538 45.571 ;
     RECT  39.276 44.681 39.294 45.571 ;
     RECT  2.376 45.571 39.294 45.995 ;
     RECT  2.376 45.995 39.042 46.013 ;
     RECT  2.415 46.013 39.042 46.885 ;
     RECT  2.376 46.885 39.042 47.371 ;
     RECT  40.215 41.909 40.497 47.371 ;
     RECT  2.376 47.371 40.497 47.659 ;
     RECT  2.34 47.659 40.497 47.891 ;
     RECT  9.828 47.891 40.497 48.119 ;
     RECT  9.828 48.119 39.294 48.389 ;
     RECT  9.828 48.389 38.97 48.533 ;
     RECT  2.34 47.891 9.018 48.731 ;
     RECT  2.376 48.731 9.018 49.009 ;
     RECT  9.828 48.533 15.462 49.009 ;
     RECT  2.376 49.009 15.462 49.279 ;
     RECT  2.376 49.279 15.57 49.315 ;
     RECT  16.38 48.533 38.97 49.315 ;
     RECT  40.215 48.119 40.497 49.963 ;
     RECT  2.376 49.315 38.97 50.017 ;
     RECT  2.376 50.017 39.042 50.125 ;
     RECT  39.852 49.963 40.497 50.125 ;
     RECT  2.376 50.125 40.497 50.431 ;
     RECT  2.376 50.431 41.166 50.549 ;
     RECT  2.376 50.549 40.698 50.819 ;
     RECT  2.415 50.819 40.698 50.855 ;
     RECT  0.108 52.015 0.126 52.177 ;
     RECT  2.415 50.855 40.497 52.177 ;
     RECT  2.415 52.177 40.698 52.321 ;
     RECT  2.34 52.321 40.878 52.547 ;
     RECT  0.108 52.177 0.234 52.825 ;
     RECT  2.34 52.547 40.497 53.401 ;
     RECT  2.304 53.401 40.497 53.429 ;
     RECT  2.304 53.429 38.142 53.519 ;
     RECT  38.88 53.429 40.497 53.519 ;
     RECT  2.304 53.519 38.07 53.555 ;
     RECT  2.304 53.555 38.034 53.591 ;
     RECT  37.8 53.591 38.034 53.627 ;
     RECT  81.828 47.611 81.846 54.031 ;
     RECT  41.328 53.527 41.346 54.059 ;
     RECT  0.108 52.825 0.27 54.067 ;
     RECT  0.108 54.067 0.306 54.103 ;
     RECT  38.952 53.519 40.497 54.173 ;
     RECT  39.528 54.173 40.497 54.211 ;
     RECT  39.528 54.211 41.274 54.329 ;
     RECT  39.528 54.329 40.842 54.365 ;
     RECT  2.304 53.591 37.026 54.607 ;
     RECT  37.8 53.627 37.818 54.607 ;
     RECT  0.108 54.103 0.342 54.797 ;
     RECT  2.304 54.607 37.818 55.021 ;
     RECT  2.304 55.021 38.034 55.111 ;
     RECT  2.304 55.111 38.79 55.181 ;
     RECT  2.304 55.181 38.178 55.277 ;
     RECT  0.288 54.797 0.342 55.373 ;
     RECT  2.304 55.277 37.818 55.627 ;
     RECT  58.428 38.251 58.77 55.771 ;
     RECT  59.796 22.621 59.814 55.771 ;
     RECT  0.144 55.675 0.162 55.795 ;
     RECT  2.268 55.627 37.818 55.859 ;
     RECT  58.428 55.771 59.814 55.859 ;
     RECT  0.108 55.795 0.162 55.949 ;
     RECT  2.268 55.859 37.494 55.949 ;
     RECT  68.868 3.839 68.886 56.219 ;
     RECT  0.144 55.949 0.162 56.285 ;
     RECT  78.015 2.413 78.297 56.371 ;
     RECT  80.676 55.417 80.694 56.731 ;
     RECT  81.828 54.031 82.386 56.731 ;
     RECT  83.415 2.413 83.697 56.731 ;
     RECT  2.268 55.949 4.986 56.779 ;
     RECT  81.828 56.731 83.697 56.831 ;
     RECT  79.524 56.731 79.542 56.839 ;
     RECT  2.232 56.779 4.986 56.875 ;
     RECT  79.524 56.839 79.866 56.875 ;
     RECT  80.64 56.731 80.694 56.875 ;
     RECT  2.196 56.875 4.986 56.911 ;
     RECT  5.76 55.949 37.494 56.911 ;
     RECT  77.508 56.371 78.297 56.911 ;
     RECT  79.524 56.875 80.694 56.911 ;
     RECT  76.968 56.911 78.39 57.037 ;
     RECT  76.716 57.037 78.39 57.145 ;
     RECT  79.308 56.911 80.694 57.145 ;
     RECT  83.415 56.831 83.697 57.181 ;
     RECT  76.716 57.145 80.694 57.209 ;
     RECT  0.108 57.163 0.126 57.389 ;
     RECT  77.508 57.209 80.694 57.415 ;
     RECT  2.196 56.911 37.494 57.451 ;
     RECT  77.508 57.415 80.874 57.451 ;
     RECT  81.828 56.831 82.134 57.451 ;
     RECT  77.508 57.451 80.946 57.479 ;
     RECT  77.94 57.479 80.946 57.541 ;
     RECT  81.72 57.451 82.134 57.541 ;
     RECT  76.716 57.209 76.734 57.581 ;
     RECT  2.196 57.451 37.53 57.641 ;
     RECT  77.94 57.541 82.134 57.641 ;
     RECT  39.528 54.365 40.497 57.749 ;
     RECT  81.684 57.641 82.134 57.811 ;
     RECT  77.94 57.641 80.874 57.839 ;
     RECT  86.292 57.541 86.31 57.869 ;
     RECT  77.94 57.839 78.93 57.911 ;
     RECT  78.015 57.911 78.93 57.947 ;
     RECT  79.956 57.839 80.874 57.947 ;
     RECT  40.215 57.749 40.497 57.979 ;
     RECT  78.015 57.947 78.822 57.983 ;
     RECT  83.415 57.181 83.898 57.991 ;
     RECT  79.956 57.947 80.802 58.109 ;
     RECT  85.464 57.919 85.482 58.109 ;
     RECT  81.684 57.811 82.242 58.117 ;
     RECT  82.98 57.991 83.898 58.117 ;
     RECT  2.196 57.641 37.494 58.145 ;
     RECT  79.956 58.109 80.658 58.145 ;
     RECT  40.215 57.979 40.59 58.157 ;
     RECT  80.64 58.145 80.658 58.157 ;
     RECT  81.684 58.117 83.898 58.157 ;
     RECT  82.224 58.157 83.898 58.181 ;
     RECT  82.548 58.181 83.898 58.379 ;
     RECT  82.548 58.379 83.862 58.415 ;
     RECT  82.98 58.415 83.862 58.649 ;
     RECT  2.304 58.145 37.494 58.699 ;
     RECT  82.98 58.649 83.697 58.955 ;
     RECT  2.304 58.699 37.782 59.503 ;
     RECT  2.304 59.503 37.818 59.729 ;
     RECT  2.304 59.729 37.674 59.765 ;
     RECT  2.304 59.765 37.494 60.575 ;
     RECT  2.376 60.575 37.494 60.961 ;
     RECT  2.376 60.961 37.782 61.079 ;
     RECT  2.376 61.079 37.494 62.573 ;
     RECT  2.415 62.573 37.494 63.121 ;
     RECT  2.415 63.121 37.566 63.661 ;
     RECT  2.415 63.661 37.926 63.779 ;
     RECT  2.415 63.779 37.494 63.959 ;
     RECT  2.415 63.959 36.702 64.903 ;
     RECT  2.34 64.903 36.702 64.931 ;
     RECT  2.34 64.931 26.766 64.973 ;
     RECT  27.504 64.931 36.702 65.011 ;
     RECT  37.476 63.959 37.494 65.011 ;
     RECT  27.504 65.011 37.494 65.399 ;
     RECT  27.504 65.399 36.378 65.435 ;
     RECT  37.296 65.399 37.494 65.669 ;
     RECT  27.504 65.435 36.162 65.741 ;
     RECT  2.415 64.973 26.766 65.749 ;
     RECT  27.504 65.741 35.946 65.749 ;
     RECT  2.415 65.749 35.946 65.813 ;
     RECT  37.332 65.669 37.494 65.813 ;
     RECT  59.796 55.859 59.814 65.821 ;
     RECT  2.415 65.813 35.73 66.269 ;
     RECT  2.415 66.269 35.406 66.289 ;
     RECT  2.376 66.289 35.406 66.551 ;
     RECT  2.376 66.551 31.302 66.623 ;
     RECT  2.376 66.623 30.978 66.749 ;
     RECT  32.112 66.551 32.994 66.941 ;
     RECT  32.256 66.941 32.994 67.019 ;
     RECT  33.804 66.551 35.406 67.019 ;
     RECT  2.415 66.749 30.978 67.091 ;
     RECT  34.668 67.019 35.406 67.127 ;
     RECT  32.58 67.019 32.994 67.199 ;
     RECT  34.815 67.127 35.406 67.325 ;
     RECT  32.76 67.199 32.994 67.405 ;
     RECT  33.804 67.019 33.822 67.405 ;
     RECT  32.76 67.405 33.822 67.829 ;
     RECT  32.904 67.829 32.994 67.865 ;
     RECT  32.976 67.865 32.994 67.901 ;
     RECT  33.804 67.829 33.822 67.973 ;
     RECT  31.752 67.981 31.77 68.099 ;
     RECT  2.415 67.091 30.942 68.179 ;
     RECT  37.476 65.813 37.494 68.207 ;
     RECT  2.415 68.179 31.554 68.549 ;
     RECT  2.415 68.549 30.87 68.675 ;
     RECT  2.415 68.675 30.69 68.909 ;
     RECT  3.42 68.909 30.222 68.945 ;
     RECT  3.42 68.945 29.97 68.981 ;
     RECT  3.42 68.981 29.754 69.251 ;
     RECT  2.415 68.909 2.697 69.643 ;
     RECT  3.42 69.251 29.697 69.643 ;
     RECT  2.415 69.643 29.697 69.719 ;
     RECT  25.38 69.719 29.697 69.791 ;
     RECT  2.415 69.719 24.57 69.989 ;
     RECT  3.42 69.989 4.734 70.025 ;
     RECT  3.42 70.025 3.438 70.061 ;
     RECT  4.176 70.025 4.662 70.061 ;
     RECT  4.572 70.061 4.662 70.097 ;
     RECT  25.416 69.791 29.697 70.331 ;
     RECT  5.544 69.989 24.57 70.529 ;
     RECT  25.416 70.331 28.638 70.799 ;
     RECT  25.416 70.799 28.206 71.069 ;
     RECT  6.084 70.529 24.57 71.311 ;
     RECT  5.616 71.311 24.57 71.357 ;
     RECT  6.3 71.357 24.57 71.419 ;
     RECT  25.416 71.069 27.378 71.419 ;
     RECT  6.3 71.419 27.378 71.645 ;
     RECT  6.3 71.645 20.646 71.753 ;
     RECT  21.456 71.645 27.378 71.885 ;
     RECT  21.456 71.885 27.342 71.915 ;
     RECT  21.456 71.915 27.162 71.96 ;
     RECT  6.3 71.753 20.538 72.419 ;
     RECT  21.456 71.96 27.054 72.427 ;
     RECT  5.868 72.421 5.886 72.461 ;
     RECT  6.84 72.419 20.538 72.527 ;
     RECT  21.384 72.427 27.054 72.527 ;
     RECT  6.912 72.527 20.538 72.571 ;
     RECT  21.384 72.527 26.766 72.571 ;
     RECT  6.912 72.571 26.766 72.689 ;
     RECT  6.912 72.689 25.29 73.229 ;
     RECT  7.128 73.229 24.354 73.373 ;
     RECT  7.272 73.373 24.354 73.841 ;
     RECT  7.272 73.841 10.314 74.039 ;
     RECT  11.304 73.841 24.354 74.075 ;
     RECT  11.412 74.075 24.354 74.083 ;
     RECT  7.272 74.039 8.514 74.093 ;
     RECT  11.412 74.083 24.642 74.111 ;
     RECT  9.648 74.039 10.206 74.309 ;
     RECT  12.096 74.111 24.642 74.309 ;
     RECT  7.488 74.093 8.514 74.333 ;
     RECT  7.488 74.333 8.097 74.345 ;
     RECT  9.648 74.309 9.666 74.345 ;
     RECT  18.252 74.309 24.297 74.345 ;
     RECT  12.096 74.309 17.514 74.489 ;
     RECT  12.096 74.489 17.478 74.579 ;
     RECT  18.252 74.345 22.986 74.615 ;
     RECT  18.252 74.615 20.574 74.621 ;
     RECT  12.096 74.579 17.442 74.651 ;
     RECT  12.096 74.651 17.406 74.723 ;
     RECT  21.42 74.615 22.986 74.885 ;
     RECT  22.968 74.885 22.986 74.957 ;
     RECT  12.096 74.723 17.262 74.965 ;
     RECT  12.024 74.965 17.262 74.993 ;
     RECT  18.252 74.621 20.538 74.993 ;
     RECT  12.024 74.993 14.958 75.005 ;
     RECT  18.252 74.993 19.278 75.029 ;
     RECT  12.276 75.005 14.958 75.119 ;
     RECT  16.128 74.993 17.262 75.155 ;
     RECT  18.615 75.029 19.278 75.155 ;
     RECT  12.276 75.119 14.814 75.191 ;
     RECT  20.088 74.993 20.538 75.191 ;
     RECT  21.42 74.885 22.122 75.191 ;
     RECT  16.488 75.155 17.262 75.227 ;
     RECT  12.276 75.191 12.438 75.299 ;
     RECT  12.276 75.299 12.366 75.389 ;
     RECT  13.215 75.191 14.814 75.389 ;
     RECT  20.088 75.191 20.394 75.389 ;
     RECT  12.276 75.389 12.294 75.425 ;
     RECT  21.672 75.191 22.122 75.425 ;
     RECT  20.268 75.389 20.394 75.461 ;
     RECT  20.376 75.461 20.394 75.569 ;
     RECT  16.524 75.227 17.262 75.659 ;
     RECT  21.744 75.425 21.87 75.659 ;
     RECT  16.524 75.659 16.542 75.695 ;
     RECT  21.744 75.659 21.762 75.695 ;
     RECT  55.044 51.205 55.062 76.739 ;
     RECT  58.428 55.859 58.77 81.499 ;
     RECT  59.688 65.821 59.814 81.499 ;
     RECT  58.428 81.499 59.814 81.571 ;
     RECT  60.804 68.647 60.822 81.571 ;
     RECT  54.36 76.891 54.378 81.671 ;
     RECT  58.428 81.571 60.822 81.751 ;
     RECT  45.615 2.413 45.897 82.111 ;
     RECT  45.504 82.111 45.897 82.157 ;
     RECT  54.72 82.123 54.738 82.253 ;
     RECT  57.816 81.751 60.822 82.409 ;
     RECT  57.816 82.409 60.174 82.561 ;
     RECT  57.492 82.561 60.174 82.985 ;
     RECT  57.852 82.985 60.174 83.219 ;
     RECT  57.852 83.219 60.066 83.759 ;
     RECT  2.415 69.989 2.697 83.987 ;
     RECT  7.815 74.345 8.097 83.987 ;
     RECT  13.215 75.389 13.497 83.987 ;
     RECT  18.615 75.155 18.897 83.987 ;
     RECT  24.015 74.345 24.297 83.987 ;
     RECT  29.415 70.331 29.697 83.987 ;
     RECT  34.815 67.325 35.097 83.987 ;
     RECT  40.215 58.157 40.497 83.987 ;
     RECT  45.615 82.157 45.897 83.987 ;
     RECT  51.015 2.413 51.297 83.987 ;
     RECT  56.415 2.413 56.697 83.987 ;
     RECT  61.815 2.413 62.097 83.987 ;
     RECT  67.215 4.109 67.497 83.987 ;
     RECT  72.615 2.413 72.897 83.987 ;
     RECT  78.015 57.983 78.297 83.987 ;
     RECT  83.415 58.955 83.697 83.987 ;
     RECT  57.852 83.759 59.562 84.209 ;
     RECT  2.415 83.987 2.505 84.257 ;
     RECT  7.815 83.987 7.905 84.257 ;
     RECT  13.215 83.987 13.305 84.257 ;
     RECT  18.615 83.987 18.705 84.257 ;
     RECT  24.015 83.987 24.105 84.257 ;
     RECT  29.415 83.987 29.505 84.257 ;
     RECT  34.815 83.987 34.905 84.257 ;
     RECT  40.215 83.987 40.305 84.257 ;
     RECT  45.615 83.987 45.705 84.257 ;
     RECT  51.015 83.987 51.105 84.257 ;
     RECT  56.415 83.987 56.505 84.257 ;
     RECT  61.815 83.987 61.905 84.257 ;
     RECT  67.215 83.987 67.305 84.257 ;
     RECT  72.615 83.987 72.705 84.257 ;
     RECT  78.015 83.987 78.105 84.257 ;
     RECT  83.415 83.987 83.505 84.257 ;
     RECT  58.5 84.209 59.562 84.365 ;
     RECT  58.5 84.365 59.454 85.517 ;
     RECT  58.824 85.517 59.454 86.285 ;
    LAYER M4 ;
     RECT  0.06 54.192 0.097 57.192 ;
     RECT  0.06 21.936 0.137 24.936 ;
     RECT  0.097 54.192 0.137 57.384 ;
     RECT  0.137 22.032 0.173 24.936 ;
     RECT  0.137 54.288 0.173 57.384 ;
     RECT  0.173 54.384 0.209 57.384 ;
     RECT  0.209 54.48 0.245 57.384 ;
     RECT  0.245 54.576 0.281 57.384 ;
     RECT  0.173 22.128 2.408 24.936 ;
     RECT  2.365 26.832 2.408 26.856 ;
     RECT  2.365 38.16 2.408 38.184 ;
     RECT  2.329 40.032 2.408 40.056 ;
     RECT  2.365 43.872 2.408 43.896 ;
     RECT  2.365 45.984 2.408 46.008 ;
     RECT  2.365 48.48 2.408 49.032 ;
     RECT  0.281 54.672 2.408 57.384 ;
     RECT  2.293 59.568 2.408 59.592 ;
     RECT  2.365 62.544 2.408 62.568 ;
     RECT  2.329 64.944 2.408 64.968 ;
     RECT  2.408 2.148 2.512 84.252 ;
     RECT  2.512 2.418 2.704 83.982 ;
     RECT  2.704 28.08 2.801 30.264 ;
     RECT  2.704 32.976 2.801 33.672 ;
     RECT  2.704 19.344 2.819 27.048 ;
     RECT  2.704 31.296 2.819 31.32 ;
     RECT  2.704 45.984 2.819 49.8 ;
     RECT  2.819 19.344 2.837 26.952 ;
     RECT  2.704 35.904 2.837 42.168 ;
     RECT  2.837 21.072 2.867 26.952 ;
     RECT  2.837 40.992 2.867 42.168 ;
     RECT  2.704 54.096 2.867 60.36 ;
     RECT  2.704 62.544 2.867 62.856 ;
     RECT  2.704 64.368 2.917 64.968 ;
     RECT  2.867 62.688 2.928 62.856 ;
     RECT  2.819 46.512 2.981 49.8 ;
     RECT  2.837 35.904 3.125 39.768 ;
     RECT  2.704 69.648 3.196 69.672 ;
     RECT  2.867 54.096 3.233 58.68 ;
     RECT  3.233 54.096 3.305 55.704 ;
     RECT  3.305 54.096 3.485 55.56 ;
     RECT  2.837 19.344 3.504 19.848 ;
     RECT  2.917 64.944 3.521 64.968 ;
     RECT  2.867 22.176 3.557 26.952 ;
     RECT  2.704 68.256 3.593 68.376 ;
     RECT  2.981 47.952 3.697 49.8 ;
     RECT  2.704 50.88 3.697 51.912 ;
     RECT  2.801 28.08 3.731 28.632 ;
     RECT  3.485 54.096 3.733 54.888 ;
     RECT  2.867 21.072 3.737 21.096 ;
     RECT  2.704 34.656 3.769 34.68 ;
     RECT  3.733 53.568 3.769 54.888 ;
     RECT  2.981 46.512 3.836 46.728 ;
     RECT  3.557 24.288 3.845 26.952 ;
     RECT  3.697 47.952 3.845 51.912 ;
     RECT  2.704 43.872 3.877 43.896 ;
     RECT  3.836 46.176 3.881 46.728 ;
     RECT  3.845 47.952 3.917 47.976 ;
     RECT  3.881 46.176 3.923 46.2 ;
     RECT  3.731 28.416 3.949 28.632 ;
     RECT  2.801 29.664 3.949 30.264 ;
     RECT  2.867 41.616 3.973 42.168 ;
     RECT  3.877 43.776 3.973 43.896 ;
     RECT  3.949 28.416 3.985 30.264 ;
     RECT  2.801 32.976 3.985 33 ;
     RECT  3.769 34.656 3.985 34.824 ;
     RECT  3.845 49.008 4.021 51.912 ;
     RECT  2.867 60.288 4.021 60.36 ;
     RECT  4.021 60.24 4.025 60.36 ;
     RECT  3.973 40.752 4.06 43.896 ;
     RECT  3.557 22.176 4.097 23.304 ;
     RECT  4.021 49.008 4.097 52.2 ;
     RECT  4.06 43.296 4.124 43.896 ;
     RECT  2.704 17.088 4.129 17.112 ;
     RECT  3.985 32.976 4.129 34.824 ;
     RECT  3.125 35.904 4.129 38.184 ;
     RECT  2.704 66.192 4.129 66.216 ;
     RECT  4.129 16.656 4.169 17.112 ;
     RECT  3.233 57.12 4.201 58.68 ;
     RECT  4.124 43.296 4.211 44.136 ;
     RECT  2.928 62.832 4.277 62.856 ;
     RECT  4.097 50.352 4.309 52.2 ;
     RECT  3.769 53.232 4.309 54.888 ;
     RECT  4.129 66.192 4.309 66.408 ;
     RECT  4.309 50.352 4.313 54.888 ;
     RECT  3.845 24.336 4.349 26.952 ;
     RECT  4.129 32.976 4.385 38.184 ;
     RECT  4.201 57.12 4.489 59.208 ;
     RECT  4.385 32.976 4.501 37.752 ;
     RECT  3.125 39.216 4.525 39.768 ;
     RECT  4.097 23.28 4.529 23.304 ;
     RECT  4.501 32.448 4.547 37.752 ;
     RECT  3.985 28.416 4.597 30.84 ;
     RECT  3.504 19.776 4.633 19.848 ;
     RECT  4.547 33.552 4.637 37.752 ;
     RECT  4.597 28.416 4.669 31.368 ;
     RECT  4.547 32.448 4.669 32.472 ;
     RECT  4.489 56.496 4.705 59.208 ;
     RECT  4.633 18.96 4.777 19.848 ;
     RECT  3.985 20.832 4.777 21.048 ;
     RECT  3.593 68.256 4.777 68.28 ;
     RECT  4.489 62.736 4.813 62.76 ;
     RECT  4.777 68.256 4.837 68.376 ;
     RECT  4.669 28.416 4.853 32.472 ;
     RECT  4.097 22.176 4.921 22.248 ;
     RECT  4.837 67.536 4.925 68.376 ;
     RECT  4.777 18.96 4.957 21.048 ;
     RECT  4.921 22.128 4.957 22.248 ;
     RECT  4.211 43.536 4.988 44.136 ;
     RECT  4.988 43.536 5.029 44.808 ;
     RECT  4.813 62.592 5.065 62.76 ;
     RECT  5.029 43.536 5.075 45.72 ;
     RECT  4.925 68.256 5.077 68.376 ;
     RECT  4.201 69.648 5.077 69.672 ;
     RECT  4.349 24.336 5.101 25.752 ;
     RECT  4.957 18.96 5.125 22.248 ;
     RECT  4.169 16.656 5.132 16.68 ;
     RECT  4.525 39.216 5.137 39.96 ;
     RECT  4.313 50.352 5.141 54.648 ;
     RECT  5.125 18.768 5.171 22.248 ;
     RECT  5.171 20.064 5.173 22.248 ;
     RECT  5.132 15.888 5.219 16.68 ;
     RECT  5.219 16.656 5.245 16.68 ;
     RECT  5.171 18.768 5.249 18.984 ;
     RECT  4.025 60.24 5.276 60.264 ;
     RECT  5.065 61.68 5.276 62.76 ;
     RECT  5.245 16.656 5.281 16.824 ;
     RECT  5.281 16.656 5.285 17.448 ;
     RECT  5.285 16.8 5.317 17.448 ;
     RECT  4.06 41.472 5.317 42.264 ;
     RECT  5.075 43.536 5.317 44.136 ;
     RECT  4.853 30.48 5.321 32.472 ;
     RECT  5.276 60.24 5.363 62.76 ;
     RECT  4.637 33.552 5.465 37.608 ;
     RECT  5.101 23.712 5.468 25.752 ;
     RECT  4.349 26.928 5.468 26.952 ;
     RECT  4.853 28.416 5.468 28.968 ;
     RECT  4.705 55.872 5.497 59.208 ;
     RECT  5.363 60.24 5.497 60.264 ;
     RECT  5.141 50.352 5.501 51.288 ;
     RECT  4.097 49.008 5.533 49.032 ;
     RECT  5.077 68.256 5.533 69.672 ;
     RECT  5.533 48.96 5.605 49.032 ;
     RECT  5.533 68.256 5.617 70.152 ;
     RECT  5.137 38.928 5.641 39.96 ;
     RECT  5.317 41.472 5.641 44.136 ;
     RECT  5.321 30.672 5.653 32.472 ;
     RECT  5.465 33.552 5.653 37.032 ;
     RECT  5.497 55.872 5.677 60.264 ;
     RECT  3.985 47.232 5.701 47.4 ;
     RECT  5.677 55.632 5.753 60.264 ;
     RECT  5.605 48.912 5.789 49.032 ;
     RECT  5.249 18.96 5.861 18.984 ;
     RECT  4.309 65.328 5.941 66.408 ;
     RECT  5.617 68.256 5.941 69.24 ;
     RECT  5.701 47.232 5.969 47.736 ;
     RECT  5.468 23.712 6.001 26.952 ;
     RECT  5.468 28.08 6.001 28.968 ;
     RECT  5.641 38.928 6.005 44.136 ;
     RECT  5.969 47.712 6.037 47.736 ;
     RECT  5.789 48.912 6.037 48.984 ;
     RECT  5.363 61.68 6.073 62.76 ;
     RECT  6.001 23.712 6.109 28.968 ;
     RECT  5.501 50.448 6.181 51.288 ;
     RECT  5.141 52.272 6.181 54.648 ;
     RECT  5.653 30.672 6.221 37.032 ;
     RECT  5.941 65.232 6.253 69.24 ;
     RECT  5.173 20.064 6.325 22.584 ;
     RECT  5.317 16.8 6.329 17.976 ;
     RECT  5.753 55.632 6.329 58.92 ;
     RECT  6.253 64.368 6.329 69.24 ;
     RECT  6.329 17.04 6.433 17.976 ;
     RECT  6.221 30.672 6.473 32.328 ;
     RECT  6.181 50.448 6.505 54.648 ;
     RECT  6.329 55.632 6.505 58.296 ;
     RECT  6.109 23.712 6.545 29.688 ;
     RECT  6.545 23.904 6.649 29.688 ;
     RECT  6.473 30.672 6.649 31.944 ;
     RECT  5.075 45.696 6.685 45.72 ;
     RECT  6.221 33.84 6.709 37.032 ;
     RECT  6.329 64.368 6.725 68.952 ;
     RECT  6.073 61.68 6.757 63.048 ;
     RECT  6.505 50.448 6.833 58.296 ;
     RECT  5.605 71.328 6.853 71.352 ;
     RECT  5.753 60.24 6.901 60.264 ;
     RECT  6.833 50.448 7.153 58.248 ;
     RECT  6.853 70.368 7.153 71.352 ;
     RECT  6.757 61.68 7.189 63.096 ;
     RECT  6.005 38.928 7.261 40.056 ;
     RECT  6.433 17.04 7.292 18.744 ;
     RECT  6.325 20.064 7.292 22.632 ;
     RECT  7.189 61.584 7.3 63.096 ;
     RECT  6.725 65.712 7.333 68.952 ;
     RECT  7.153 70.368 7.333 71.448 ;
     RECT  6.901 59.472 7.381 60.264 ;
     RECT  7.3 61.536 7.381 63.096 ;
     RECT  7.261 38.928 7.405 40.44 ;
     RECT  6.709 33.84 7.441 37.608 ;
     RECT  7.292 17.04 7.477 22.632 ;
     RECT  7.441 33.36 7.513 37.608 ;
     RECT  7.513 33.264 7.585 37.608 ;
     RECT  7.405 38.736 7.621 40.44 ;
     RECT  6.005 41.424 7.621 44.136 ;
     RECT  7.225 13.104 7.657 13.128 ;
     RECT  7.477 17.04 7.669 22.776 ;
     RECT  6.649 23.904 7.669 31.944 ;
     RECT  7.585 33.264 7.669 37.704 ;
     RECT  7.621 38.736 7.669 44.136 ;
     RECT  7.381 11.04 7.765 11.064 ;
     RECT  7.765 11.04 7.808 11.16 ;
     RECT  7.657 13.104 7.808 13.656 ;
     RECT  7.477 15.312 7.808 15.336 ;
     RECT  7.669 17.04 7.808 31.944 ;
     RECT  7.669 33.264 7.808 44.136 ;
     RECT  6.685 45.696 7.808 46.584 ;
     RECT  6.037 47.712 7.808 48.984 ;
     RECT  7.153 50.064 7.808 58.248 ;
     RECT  7.381 59.472 7.808 63.096 ;
     RECT  6.725 64.368 7.808 64.728 ;
     RECT  7.333 65.712 7.808 71.448 ;
     RECT  5.857 72.432 7.808 72.456 ;
     RECT  7.261 74.064 7.808 74.088 ;
     RECT  7.808 2.148 7.912 84.252 ;
     RECT  7.912 2.418 8.104 83.982 ;
     RECT  8.104 24.096 8.201 31.464 ;
     RECT  8.104 46.368 8.237 54.36 ;
     RECT  8.104 55.392 8.273 55.8 ;
     RECT  8.201 30.672 8.309 31.464 ;
     RECT  8.104 32.448 8.345 39.912 ;
     RECT  8.104 16.56 8.381 22.776 ;
     RECT  8.345 36.096 8.381 39.912 ;
     RECT  8.381 16.56 8.387 16.584 ;
     RECT  8.104 41.472 8.483 45.384 ;
     RECT  8.309 30.672 8.489 31.416 ;
     RECT  8.237 48.96 8.489 54.36 ;
     RECT  8.273 55.392 8.489 55.704 ;
     RECT  8.104 74.064 8.525 74.328 ;
     RECT  8.489 55.392 8.561 55.416 ;
     RECT  8.104 12.528 8.579 14.28 ;
     RECT  8.381 17.952 8.597 22.776 ;
     RECT  8.201 24.096 8.597 29.352 ;
     RECT  8.489 49.2 8.597 54.36 ;
     RECT  8.104 57.024 8.627 63.288 ;
     RECT  8.597 49.2 8.669 53.016 ;
     RECT  8.627 57.024 8.777 60.456 ;
     RECT  8.104 15.312 9.097 15.336 ;
     RECT  8.381 37.056 9.097 39.912 ;
     RECT  8.597 19.728 9.109 22.776 ;
     RECT  8.237 46.368 9.169 47.88 ;
     RECT  8.597 28.704 9.173 29.352 ;
     RECT  9.097 37.056 9.209 39.96 ;
     RECT  8.483 41.472 9.209 45 ;
     RECT  8.104 65.712 9.241 68.712 ;
     RECT  9.133 70.032 9.241 70.056 ;
     RECT  8.777 57.024 9.277 58.2 ;
     RECT  8.489 30.672 9.349 30.84 ;
     RECT  8.104 71.568 9.349 71.592 ;
     RECT  8.597 17.952 9.385 18.744 ;
     RECT  8.627 61.872 9.389 63.288 ;
     RECT  9.385 17.664 9.457 18.744 ;
     RECT  8.597 54.096 9.457 54.36 ;
     RECT  9.173 29.136 9.493 29.352 ;
     RECT  9.349 30.48 9.493 30.84 ;
     RECT  8.669 49.2 9.533 49.608 ;
     RECT  9.457 54.096 9.541 54.744 ;
     RECT  9.209 41.472 9.565 44.424 ;
     RECT  9.533 49.2 9.565 49.416 ;
     RECT  9.205 64.368 9.565 64.392 ;
     RECT  9.241 65.712 9.565 70.056 ;
     RECT  9.493 29.136 9.637 31.032 ;
     RECT  8.345 32.448 9.637 35.064 ;
     RECT  9.637 29.136 9.677 35.064 ;
     RECT  8.777 59.472 9.683 60.456 ;
     RECT  9.389 62.544 9.709 63.288 ;
     RECT  9.565 64.368 9.709 70.056 ;
     RECT  9.209 37.872 9.713 39.96 ;
     RECT  8.597 24.096 9.745 27.48 ;
     RECT  9.541 54.096 9.779 54.168 ;
     RECT  9.457 17.472 9.781 18.744 ;
     RECT  9.109 19.728 9.781 22.824 ;
     RECT  9.709 62.544 10.001 70.056 ;
     RECT  8.669 50.88 10.033 53.016 ;
     RECT  9.781 17.472 10.037 22.824 ;
     RECT  9.713 38.112 10.069 39.96 ;
     RECT  9.349 71.424 10.069 71.592 ;
     RECT  10.037 19.728 10.073 22.824 ;
     RECT  8.579 12.624 10.105 14.28 ;
     RECT  9.097 15.312 10.105 16.008 ;
     RECT  9.677 29.136 10.145 31.896 ;
     RECT  9.779 54.096 10.181 54.12 ;
     RECT  9.169 46.128 10.213 47.88 ;
     RECT  9.565 49.104 10.213 49.416 ;
     RECT  10.213 46.128 10.22 49.416 ;
     RECT  9.565 41.376 10.261 44.424 ;
     RECT  9.097 72.768 10.261 72.792 ;
     RECT  8.525 74.304 10.261 74.328 ;
     RECT  9.677 33.024 10.289 35.064 ;
     RECT  10.261 72.768 10.307 74.328 ;
     RECT  10.289 33.024 10.325 34.872 ;
     RECT  10.069 71.376 10.393 71.592 ;
     RECT  10.307 72.768 10.393 73.512 ;
     RECT  10.001 62.544 10.396 69.624 ;
     RECT  10.145 29.136 10.429 31.032 ;
     RECT  9.745 24.096 10.465 27.816 ;
     RECT  10.429 28.992 10.465 31.032 ;
     RECT  10.396 62.544 10.465 64.728 ;
     RECT  10.508 36.24 10.549 36.264 ;
     RECT  10.549 36.24 10.595 37.08 ;
     RECT  10.033 50.688 10.609 53.016 ;
     RECT  9.277 56.832 10.609 58.2 ;
     RECT  9.683 59.472 10.609 60.12 ;
     RECT  10.393 71.376 10.609 73.512 ;
     RECT  10.22 45.648 10.645 49.416 ;
     RECT  10.069 55.44 10.645 55.704 ;
     RECT  10.609 56.832 10.645 60.12 ;
     RECT  10.105 12.624 10.649 16.008 ;
     RECT  10.069 38.112 10.649 40.056 ;
     RECT  10.649 38.784 10.753 40.056 ;
     RECT  10.261 41.376 10.753 44.472 ;
     RECT  10.753 38.784 10.789 44.472 ;
     RECT  10.645 45.504 10.789 49.416 ;
     RECT  10.325 33.12 10.793 34.872 ;
     RECT  10.789 38.784 10.847 49.416 ;
     RECT  10.609 50.688 10.847 53.688 ;
     RECT  8.104 11.136 10.861 11.496 ;
     RECT  10.649 12.624 10.861 15.432 ;
     RECT  10.465 62.304 10.865 64.728 ;
     RECT  10.865 62.304 10.925 63.672 ;
     RECT  10.847 38.784 10.931 53.688 ;
     RECT  10.931 38.784 10.937 48.216 ;
     RECT  10.595 36.432 11.005 37.08 ;
     RECT  10.925 62.208 11.005 63.672 ;
     RECT  10.609 71.328 11.081 73.512 ;
     RECT  10.037 17.472 11.113 18.168 ;
     RECT  10.073 19.92 11.113 22.824 ;
     RECT  10.465 24.096 11.113 31.032 ;
     RECT  11.113 17.04 11.117 18.168 ;
     RECT  10.645 55.44 11.149 60.12 ;
     RECT  11.005 9.936 11.185 9.96 ;
     RECT  10.861 11.136 11.185 15.432 ;
     RECT  11.117 17.04 11.189 17.688 ;
     RECT  10.865 64.704 11.189 64.728 ;
     RECT  11.189 17.04 11.197 17.496 ;
     RECT  11.113 19.92 11.221 31.032 ;
     RECT  11.221 19.92 11.297 31.416 ;
     RECT  11.297 19.92 11.329 24.12 ;
     RECT  10.396 65.712 11.477 69.624 ;
     RECT  11.149 55.44 11.513 60.552 ;
     RECT  11.005 61.632 11.549 63.672 ;
     RECT  10.931 49.392 11.581 53.688 ;
     RECT  11.477 65.712 11.585 69.384 ;
     RECT  10.793 33.12 11.657 34.152 ;
     RECT  11.585 67.248 11.729 69.384 ;
     RECT  11.081 71.328 11.749 73.416 ;
     RECT  11.185 9.936 11.761 15.432 ;
     RECT  10.937 38.784 11.765 44.952 ;
     RECT  11.729 67.296 11.795 69.384 ;
     RECT  11.765 41.424 11.801 44.952 ;
     RECT  11.761 9.936 11.804 16.344 ;
     RECT  11.795 67.296 11.837 69.336 ;
     RECT  11.549 61.632 11.869 63.624 ;
     RECT  11.804 9.648 11.891 16.344 ;
     RECT  11.837 67.344 11.909 69.336 ;
     RECT  11.801 42 11.941 44.952 ;
     RECT  10.937 46.128 11.941 48.216 ;
     RECT  11.005 36.432 11.977 37.416 ;
     RECT  11.977 35.568 12.085 37.416 ;
     RECT  11.765 38.784 12.085 40.056 ;
     RECT  11.585 65.712 12.085 66.216 ;
     RECT  11.749 70.656 12.089 73.416 ;
     RECT  11.197 17.376 12.197 17.496 ;
     RECT  12.085 65.664 12.229 66.216 ;
     RECT  12.089 70.656 12.229 72.504 ;
     RECT  11.581 49.392 12.337 54.12 ;
     RECT  11.329 19.248 12.481 24.12 ;
     RECT  12.337 49.392 12.517 54.552 ;
     RECT  11.513 55.68 12.517 60.552 ;
     RECT  12.517 49.392 12.553 60.552 ;
     RECT  11.869 61.584 12.553 63.624 ;
     RECT  12.481 18.768 12.613 24.12 ;
     RECT  11.297 25.44 12.613 31.416 ;
     RECT  12.613 18.768 12.625 31.416 ;
     RECT  12.085 35.568 12.697 40.056 ;
     RECT  12.697 35.328 12.877 40.056 ;
     RECT  12.229 65.52 12.913 66.216 ;
     RECT  11.909 67.776 12.913 69.336 ;
     RECT  11.941 42 12.997 48.216 ;
     RECT  12.553 49.296 12.997 63.816 ;
     RECT  12.913 65.52 13.093 69.336 ;
     RECT  11.891 9.792 13.129 16.344 ;
     RECT  12.197 17.376 13.129 17.448 ;
     RECT  13.129 9.792 13.208 17.448 ;
     RECT  12.625 18.768 13.208 31.944 ;
     RECT  11.657 33.888 13.208 34.152 ;
     RECT  12.877 35.328 13.208 40.344 ;
     RECT  12.997 42 13.208 63.816 ;
     RECT  13.093 65.52 13.208 69.432 ;
     RECT  12.229 70.464 13.208 72.504 ;
     RECT  11.949 74.976 13.208 75 ;
     RECT  13.208 2.148 13.312 84.252 ;
     RECT  13.312 2.418 13.504 83.982 ;
     RECT  13.504 35.232 13.619 41.064 ;
     RECT  13.504 16.32 13.709 34.2 ;
     RECT  13.709 16.32 13.715 33.384 ;
     RECT  13.504 61.584 13.781 63.816 ;
     RECT  13.715 18.768 13.817 33.384 ;
     RECT  13.504 68.112 13.853 72.504 ;
     RECT  13.853 68.112 13.961 72.264 ;
     RECT  13.504 9.072 13.997 10.584 ;
     RECT  13.504 42.144 14.033 50.904 ;
     RECT  13.619 35.232 14.069 35.784 ;
     RECT  14.033 48.864 14.141 50.904 ;
     RECT  13.997 9.072 14.147 9.816 ;
     RECT  13.715 16.32 14.213 17.64 ;
     RECT  14.213 16.416 14.243 17.64 ;
     RECT  14.141 48.912 14.243 50.904 ;
     RECT  13.961 69.984 14.249 70.68 ;
     RECT  14.243 16.56 14.321 17.64 ;
     RECT  13.504 58.656 14.357 59.208 ;
     RECT  13.504 51.936 14.435 57.432 ;
     RECT  14.147 9.312 14.465 9.816 ;
     RECT  14.435 54.096 14.465 57.432 ;
     RECT  14.243 49.296 14.533 50.904 ;
     RECT  14.435 51.936 14.533 52.728 ;
     RECT  13.504 12.048 14.537 15.048 ;
     RECT  13.504 74.304 14.537 75.24 ;
     RECT  14.357 59.184 14.605 59.208 ;
     RECT  13.504 60.288 14.605 60.312 ;
     RECT  14.537 12.048 14.609 12.072 ;
     RECT  14.533 49.296 14.645 52.728 ;
     RECT  14.605 59.184 14.713 60.312 ;
     RECT  13.817 18.768 14.789 33.048 ;
     RECT  13.619 36.816 14.789 41.064 ;
     RECT  14.789 37.344 14.821 41.064 ;
     RECT  14.033 42.144 14.821 47.736 ;
     RECT  13.961 68.112 14.825 69 ;
     RECT  13.961 71.76 14.893 72.264 ;
     RECT  14.825 68.112 14.897 68.712 ;
     RECT  14.537 13.104 14.933 15.048 ;
     RECT  14.821 37.344 15.005 47.736 ;
     RECT  13.781 61.584 15.037 61.608 ;
     RECT  13.781 62.736 15.037 63.816 ;
     RECT  14.713 59.184 15.109 60.6 ;
     RECT  15.037 61.584 15.109 63.816 ;
     RECT  14.069 35.424 15.181 35.784 ;
     RECT  13.504 64.896 15.253 66.744 ;
     RECT  14.789 18.768 15.293 33 ;
     RECT  14.465 55.104 15.293 57.432 ;
     RECT  15.253 64.896 15.299 67.224 ;
     RECT  14.321 16.56 15.325 17.448 ;
     RECT  15.293 18.768 15.325 27.144 ;
     RECT  15.109 59.184 15.361 63.816 ;
     RECT  15.299 64.896 15.361 66.12 ;
     RECT  15.293 55.104 15.365 55.8 ;
     RECT  14.465 9.312 15.433 9.336 ;
     RECT  15.361 59.184 15.437 66.12 ;
     RECT  14.537 74.352 15.443 75.24 ;
     RECT  15.443 74.352 15.541 75.144 ;
     RECT  15.325 16.56 15.545 27.144 ;
     RECT  15.145 11.28 15.577 11.304 ;
     RECT  15.437 59.184 15.587 59.976 ;
     RECT  15.577 11.28 15.685 11.544 ;
     RECT  14.933 13.104 15.721 14.952 ;
     RECT  14.893 71.76 15.793 72.936 ;
     RECT  15.541 74.256 15.793 75.144 ;
     RECT  15.721 12.528 15.827 14.952 ;
     RECT  15.365 55.536 15.827 55.8 ;
     RECT  15.433 9.216 15.829 9.336 ;
     RECT  15.293 28.224 15.833 33 ;
     RECT  14.249 70.272 15.937 70.296 ;
     RECT  15.545 16.56 15.941 18.936 ;
     RECT  15.829 9.216 15.973 9.576 ;
     RECT  15.685 10.896 16.009 11.544 ;
     RECT  14.645 49.296 16.009 52.296 ;
     RECT  15.937 70.032 16.009 70.296 ;
     RECT  15.545 20.016 16.013 27.144 ;
     RECT  15.293 56.832 16.017 57.432 ;
     RECT  15.833 28.416 16.069 33 ;
     RECT  15.973 9.216 16.085 9.864 ;
     RECT  15.181 34.8 16.117 35.784 ;
     RECT  16.117 34.8 16.121 36.456 ;
     RECT  16.085 9.216 16.153 9.576 ;
     RECT  16.069 28.416 16.156 33.624 ;
     RECT  15.827 13.344 16.22 14.952 ;
     RECT  15.941 16.56 16.22 17.16 ;
     RECT  16.153 9.072 16.225 9.576 ;
     RECT  16.013 26.736 16.309 27.144 ;
     RECT  15.827 55.536 16.333 55.704 ;
     RECT  14.897 68.688 16.369 68.712 ;
     RECT  16.009 69.84 16.369 70.296 ;
     RECT  15.005 37.68 16.373 47.736 ;
     RECT  16.017 56.832 16.405 58.152 ;
     RECT  15.587 59.184 16.405 59.496 ;
     RECT  16.225 8.544 16.501 9.576 ;
     RECT  15.299 67.2 16.549 67.224 ;
     RECT  16.369 68.688 16.549 70.296 ;
     RECT  16.549 67.2 16.595 70.296 ;
     RECT  16.595 67.728 16.645 70.296 ;
     RECT  15.793 71.328 16.645 75.144 ;
     RECT  16.333 55.44 16.657 55.704 ;
     RECT  16.645 67.728 16.741 75.144 ;
     RECT  16.373 37.68 16.765 38.28 ;
     RECT  15.437 60.96 16.765 66.12 ;
     RECT  16.741 71.328 16.769 75.144 ;
     RECT  16.309 26.736 16.801 27.384 ;
     RECT  16.156 28.416 16.801 32.76 ;
     RECT  16.121 35.28 16.837 36.456 ;
     RECT  16.765 37.632 16.837 38.28 ;
     RECT  16.769 71.376 16.841 75.144 ;
     RECT  16.22 13.344 16.945 17.16 ;
     RECT  15.941 18.24 16.945 18.936 ;
     RECT  16.373 39.744 16.949 47.736 ;
     RECT  16.009 10.896 17.053 12.024 ;
     RECT  16.009 49.296 17.053 52.728 ;
     RECT  16.945 13.344 17.089 18.936 ;
     RECT  16.013 20.016 17.089 25.752 ;
     RECT  17.089 13.344 17.093 25.752 ;
     RECT  16.949 43.632 17.093 47.736 ;
     RECT  16.765 60.96 17.129 66.168 ;
     RECT  16.501 8.496 17.161 9.576 ;
     RECT  16.741 67.728 17.165 70.296 ;
     RECT  17.093 13.872 17.228 25.752 ;
     RECT  16.801 26.736 17.228 32.76 ;
     RECT  17.228 13.872 17.233 32.76 ;
     RECT  17.161 8.496 17.269 9.816 ;
     RECT  17.053 10.896 17.269 12.072 ;
     RECT  16.841 71.904 17.273 75.144 ;
     RECT  16.405 56.832 17.377 59.496 ;
     RECT  17.129 60.96 17.377 66.12 ;
     RECT  17.053 49.008 17.449 52.728 ;
     RECT  17.269 8.496 17.489 12.072 ;
     RECT  14.465 54.096 17.593 54.12 ;
     RECT  16.657 55.248 17.593 55.704 ;
     RECT  17.233 13.872 17.629 33.048 ;
     RECT  17.593 54.096 17.701 55.704 ;
     RECT  17.701 53.808 18.061 55.704 ;
     RECT  17.377 56.832 18.061 66.12 ;
     RECT  17.093 43.968 18.169 47.736 ;
     RECT  16.837 35.28 18.205 38.28 ;
     RECT  16.949 39.744 18.205 42.648 ;
     RECT  17.629 13.872 18.385 33.912 ;
     RECT  17.449 48.96 18.421 52.728 ;
     RECT  18.061 53.808 18.421 66.12 ;
     RECT  17.165 67.776 18.565 70.296 ;
     RECT  17.489 8.544 18.608 12.072 ;
     RECT  18.385 13.872 18.608 33.96 ;
     RECT  18.205 34.944 18.608 38.28 ;
     RECT  18.205 39.744 18.608 42.744 ;
     RECT  18.169 43.968 18.608 47.976 ;
     RECT  18.421 48.96 18.608 66.12 ;
     RECT  18.565 67.296 18.608 70.296 ;
     RECT  17.273 71.904 18.608 74.76 ;
     RECT  18.608 2.148 18.712 84.252 ;
     RECT  18.712 2.418 18.904 83.982 ;
     RECT  18.904 56.736 19.037 65.496 ;
     RECT  18.904 66.768 19.043 75.144 ;
     RECT  18.904 33.552 19.073 53.976 ;
     RECT  18.904 21.408 19.101 32.328 ;
     RECT  18.904 8.688 19.109 12.072 ;
     RECT  19.073 33.552 19.181 52.056 ;
     RECT  19.101 31.824 19.187 32.328 ;
     RECT  19.187 31.92 19.289 32.328 ;
     RECT  19.043 66.816 19.289 75.144 ;
     RECT  19.289 66.816 19.325 74.952 ;
     RECT  19.181 33.552 19.361 48.12 ;
     RECT  19.037 56.736 19.379 62.52 ;
     RECT  19.325 68.448 19.379 74.952 ;
     RECT  19.379 62.16 19.397 62.52 ;
     RECT  18.904 13.056 19.42 20.424 ;
     RECT  19.289 32.208 19.433 32.328 ;
     RECT  19.073 53.04 19.433 53.976 ;
     RECT  19.037 64.08 19.433 65.496 ;
     RECT  19.101 21.408 19.505 30.84 ;
     RECT  19.361 33.552 19.505 38.28 ;
     RECT  19.433 64.08 19.541 65.448 ;
     RECT  19.505 21.408 19.613 30.744 ;
     RECT  19.181 49.296 19.677 52.056 ;
     RECT  19.613 21.408 19.685 30.408 ;
     RECT  19.541 64.08 19.685 65.256 ;
     RECT  19.433 53.136 19.811 53.976 ;
     RECT  19.361 39.408 19.829 48.12 ;
     RECT  19.811 53.136 19.837 53.928 ;
     RECT  19.379 68.496 19.907 74.952 ;
     RECT  19.677 49.488 19.937 52.056 ;
     RECT  19.685 21.408 19.973 29.688 ;
     RECT  19.907 71.28 19.973 74.952 ;
     RECT  19.109 8.688 20.005 11.88 ;
     RECT  19.42 13.344 20.005 20.424 ;
     RECT  19.973 21.408 20.005 28.488 ;
     RECT  18.904 54.96 20.009 55.704 ;
     RECT  20.005 13.344 20.081 28.488 ;
     RECT  19.907 68.496 20.081 69.672 ;
     RECT  19.973 29.664 20.153 29.688 ;
     RECT  19.837 53.328 20.153 53.928 ;
     RECT  20.009 55.488 20.185 55.704 ;
     RECT  19.379 56.736 20.185 60.84 ;
     RECT  19.397 62.496 20.185 62.52 ;
     RECT  20.081 68.64 20.189 69.672 ;
     RECT  20.005 8.448 20.221 11.88 ;
     RECT  19.829 39.408 20.243 48.072 ;
     RECT  20.221 8.448 20.333 12.072 ;
     RECT  20.153 53.568 20.369 53.928 ;
     RECT  19.505 35.712 20.401 38.28 ;
     RECT  20.243 39.408 20.401 44.424 ;
     RECT  20.333 9.792 20.405 12.072 ;
     RECT  20.185 55.488 20.437 60.84 ;
     RECT  19.433 32.208 20.473 32.28 ;
     RECT  20.405 10.224 20.477 12.072 ;
     RECT  19.973 71.28 20.477 74.856 ;
     RECT  20.185 62.496 20.509 62.568 ;
     RECT  20.369 53.568 20.513 53.88 ;
     RECT  20.477 74.448 20.513 74.856 ;
     RECT  20.477 10.224 20.549 11.88 ;
     RECT  20.509 62.304 20.581 62.568 ;
     RECT  20.513 74.448 20.585 74.616 ;
     RECT  19.685 64.656 20.729 65.256 ;
     RECT  19.325 66.816 20.833 67.416 ;
     RECT  20.473 31.872 20.941 32.28 ;
     RECT  19.505 33.552 20.941 34.728 ;
     RECT  20.833 66.528 20.945 67.416 ;
     RECT  20.189 68.64 20.981 69.528 ;
     RECT  20.941 31.872 21.013 34.728 ;
     RECT  20.243 45.744 21.013 48.072 ;
     RECT  20.081 13.344 21.085 28.44 ;
     RECT  21.013 31.2 21.089 34.728 ;
     RECT  20.729 65.232 21.089 65.256 ;
     RECT  21.013 45.744 21.109 48.408 ;
     RECT  19.937 49.488 21.109 51.816 ;
     RECT  21.085 13.344 21.125 28.488 ;
     RECT  21.109 45.744 21.155 51.816 ;
     RECT  21.089 32.256 21.265 34.728 ;
     RECT  20.401 35.712 21.265 44.424 ;
     RECT  20.477 71.28 21.265 73.368 ;
     RECT  20.581 62.16 21.301 62.568 ;
     RECT  20.437 55.488 21.305 61.032 ;
     RECT  20.981 68.688 21.377 69.528 ;
     RECT  20.945 66.528 21.517 67.272 ;
     RECT  21.155 45.744 21.553 49.704 ;
     RECT  21.125 13.392 21.589 28.488 ;
     RECT  21.517 66.384 21.589 67.272 ;
     RECT  20.585 74.448 21.593 74.472 ;
     RECT  20.549 11.184 21.665 11.88 ;
     RECT  21.305 56.784 21.665 61.032 ;
     RECT  20.513 53.856 21.701 53.88 ;
     RECT  21.665 56.784 21.701 58.008 ;
     RECT  20.333 8.448 21.733 8.472 ;
     RECT  21.697 9.648 21.733 9.672 ;
     RECT  21.265 32.256 21.737 44.424 ;
     RECT  21.733 8.448 21.773 9.672 ;
     RECT  21.665 11.424 21.841 11.88 ;
     RECT  21.589 13.392 21.841 29.112 ;
     RECT  21.155 50.784 21.845 51.816 ;
     RECT  21.553 45.552 21.881 49.704 ;
     RECT  21.845 50.784 21.953 51.624 ;
     RECT  21.665 59.184 21.973 61.032 ;
     RECT  21.301 62.16 21.973 62.76 ;
     RECT  21.773 9.264 21.985 9.672 ;
     RECT  21.973 59.184 22.019 62.76 ;
     RECT  21.841 13.392 22.025 29.88 ;
     RECT  21.377 68.784 22.093 69.528 ;
     RECT  21.265 70.896 22.093 73.368 ;
     RECT  21.881 49.056 22.165 49.704 ;
     RECT  21.953 50.784 22.165 51.24 ;
     RECT  21.089 31.2 22.169 31.224 ;
     RECT  22.019 59.184 22.169 62.328 ;
     RECT  22.025 13.392 22.313 15.864 ;
     RECT  21.589 66.288 22.345 67.272 ;
     RECT  21.985 9.264 22.385 10.392 ;
     RECT  22.313 13.392 22.385 15.768 ;
     RECT  21.737 32.256 22.385 33.672 ;
     RECT  22.025 16.896 22.421 29.88 ;
     RECT  22.165 53.808 22.421 53.832 ;
     RECT  22.345 66.288 22.421 67.8 ;
     RECT  22.421 16.896 22.457 29.784 ;
     RECT  22.165 49.056 22.457 51.24 ;
     RECT  21.737 34.704 22.489 44.424 ;
     RECT  21.881 45.552 22.489 47.784 ;
     RECT  22.385 9.264 22.493 9.288 ;
     RECT  22.489 34.704 22.493 47.784 ;
     RECT  22.457 49.2 22.493 51.24 ;
     RECT  22.493 49.248 22.565 51.24 ;
     RECT  22.421 67.776 22.597 67.8 ;
     RECT  22.093 68.784 22.597 69.624 ;
     RECT  22.493 34.704 22.601 47.736 ;
     RECT  22.601 34.704 22.745 47.352 ;
     RECT  22.385 32.592 22.777 33.672 ;
     RECT  22.745 34.704 22.777 47.208 ;
     RECT  22.457 16.896 22.781 27.96 ;
     RECT  21.305 55.488 22.813 55.8 ;
     RECT  21.701 56.784 22.813 57.96 ;
     RECT  22.093 70.704 22.853 73.368 ;
     RECT  22.385 10.368 22.921 10.392 ;
     RECT  21.841 11.424 22.921 11.976 ;
     RECT  22.565 49.44 23.029 51.24 ;
     RECT  23.029 49.44 23.101 51.288 ;
     RECT  23.101 49.44 23.137 52.2 ;
     RECT  22.813 55.488 23.137 57.96 ;
     RECT  22.597 67.776 23.137 69.624 ;
     RECT  22.853 70.704 23.137 72.792 ;
     RECT  23.137 55.488 23.245 58.152 ;
     RECT  23.245 54.912 23.281 58.152 ;
     RECT  22.169 59.28 23.281 62.328 ;
     RECT  22.385 13.392 23.461 15.288 ;
     RECT  22.921 10.368 23.533 11.976 ;
     RECT  23.461 13.392 23.533 15.48 ;
     RECT  22.777 32.592 23.533 47.208 ;
     RECT  23.533 10.368 23.641 15.48 ;
     RECT  22.781 16.896 23.641 27.912 ;
     RECT  23.137 49.44 23.641 52.728 ;
     RECT  23.641 49.296 23.749 52.728 ;
     RECT  23.281 54.912 23.804 62.328 ;
     RECT  23.804 54.912 23.845 62.616 ;
     RECT  23.749 63.984 23.845 64.008 ;
     RECT  23.845 54.912 23.857 64.008 ;
     RECT  23.304 8.832 24.008 8.856 ;
     RECT  23.641 10.368 24.008 27.912 ;
     RECT  22.457 29.088 24.008 29.64 ;
     RECT  23.533 31.968 24.008 47.208 ;
     RECT  23.749 49.296 24.008 53.544 ;
     RECT  23.857 54.672 24.008 64.008 ;
     RECT  22.421 66.288 24.008 66.312 ;
     RECT  23.137 67.776 24.008 72.792 ;
     RECT  23.677 74.112 24.008 74.136 ;
     RECT  24.008 2.148 24.112 84.252 ;
     RECT  24.112 2.418 24.304 83.982 ;
     RECT  24.304 32.208 24.329 60.36 ;
     RECT  24.304 20.592 24.401 29.64 ;
     RECT  24.304 71.808 24.419 74.136 ;
     RECT  24.419 71.808 24.46 72.6 ;
     RECT  24.401 20.592 24.473 29.064 ;
     RECT  24.473 25.248 24.481 29.064 ;
     RECT  24.304 18.144 24.545 18.888 ;
     RECT  24.329 59.76 24.545 60.36 ;
     RECT  24.304 10.896 24.689 16.92 ;
     RECT  24.689 10.896 24.725 10.968 ;
     RECT  24.329 32.208 24.761 58.728 ;
     RECT  24.761 32.208 24.797 53.592 ;
     RECT  24.473 20.592 24.869 23.928 ;
     RECT  24.46 72.384 24.905 72.6 ;
     RECT  24.761 54.72 24.941 58.728 ;
     RECT  24.797 33.072 25.013 53.592 ;
     RECT  24.689 12.528 25.057 16.92 ;
     RECT  24.481 26.832 25.085 29.064 ;
     RECT  25.013 33.072 25.085 53.544 ;
     RECT  24.941 58.656 25.085 58.728 ;
     RECT  25.085 33.072 25.093 50.856 ;
     RECT  24.905 72.384 25.093 72.408 ;
     RECT  24.545 18.528 25.333 18.888 ;
     RECT  24.725 10.896 25.337 10.92 ;
     RECT  25.057 12.528 25.337 15.768 ;
     RECT  25.085 58.656 25.337 58.68 ;
     RECT  25.337 12.528 25.475 13.608 ;
     RECT  24.304 68.208 25.477 68.952 ;
     RECT  25.333 18.528 25.481 18.936 ;
     RECT  25.093 34.752 25.481 50.856 ;
     RECT  24.304 65.664 25.484 66.792 ;
     RECT  24.545 59.808 25.553 60.36 ;
     RECT  25.484 65.472 25.571 66.792 ;
     RECT  24.304 61.392 25.621 63.672 ;
     RECT  25.093 33.072 25.661 33.576 ;
     RECT  25.477 68.16 25.661 68.952 ;
     RECT  24.869 20.592 25.697 23.88 ;
     RECT  24.481 25.248 25.729 25.752 ;
     RECT  25.085 26.832 25.769 28.488 ;
     RECT  25.697 20.592 25.801 22.824 ;
     RECT  25.724 11.088 25.811 11.112 ;
     RECT  25.475 13.248 25.811 13.608 ;
     RECT  25.571 65.808 25.945 66.792 ;
     RECT  25.057 16.896 25.949 16.92 ;
     RECT  25.621 60.432 25.955 63.672 ;
     RECT  25.661 33.072 25.981 33.096 ;
     RECT  25.801 20.4 25.985 22.824 ;
     RECT  25.945 65.808 26.017 66.84 ;
     RECT  25.981 32.448 26.021 33.096 ;
     RECT  26.021 32.448 26.089 33.048 ;
     RECT  25.661 68.16 26.093 68.904 ;
     RECT  25.985 21.216 26.129 22.824 ;
     RECT  25.697 23.856 26.197 23.88 ;
     RECT  25.769 26.832 26.197 27.672 ;
     RECT  24.941 54.72 26.197 57.624 ;
     RECT  25.481 34.752 26.204 38.28 ;
     RECT  25.481 39.36 26.269 50.856 ;
     RECT  25.085 51.888 26.269 53.544 ;
     RECT  26.204 34.512 26.291 38.28 ;
     RECT  26.269 39.36 26.305 53.544 ;
     RECT  26.305 39.36 26.341 53.592 ;
     RECT  25.801 71.232 26.377 71.256 ;
     RECT  25.811 13.296 26.389 13.608 ;
     RECT  26.197 54.72 26.417 58.104 ;
     RECT  26.389 13.296 26.476 13.944 ;
     RECT  26.341 39.36 26.521 53.688 ;
     RECT  26.017 65.808 26.521 67.176 ;
     RECT  26.521 65.808 26.549 67.848 ;
     RECT  25.955 60.432 26.557 61.08 ;
     RECT  26.549 65.616 26.561 67.848 ;
     RECT  26.341 59.232 26.588 59.256 ;
     RECT  26.557 60.384 26.588 61.08 ;
     RECT  26.521 39.36 26.627 54.216 ;
     RECT  25.481 18.528 26.633 18.552 ;
     RECT  26.561 65.616 26.665 66.792 ;
     RECT  25.337 14.976 26.669 15.768 ;
     RECT  25.955 62.064 26.669 63.672 ;
     RECT  26.588 59.232 26.675 61.08 ;
     RECT  26.089 31.776 26.677 33.048 ;
     RECT  26.417 55.488 26.701 58.104 ;
     RECT  26.675 59.232 26.701 59.256 ;
     RECT  26.197 23.856 26.737 24.024 ;
     RECT  25.729 25.152 26.737 25.752 ;
     RECT  26.197 16.752 26.741 16.776 ;
     RECT  26.665 65.568 26.771 66.792 ;
     RECT  26.129 21.936 26.773 22.824 ;
     RECT  26.737 23.856 26.773 25.752 ;
     RECT  26.669 14.976 26.777 15.48 ;
     RECT  26.561 67.824 26.813 67.848 ;
     RECT  26.669 62.064 26.849 63.192 ;
     RECT  26.849 62.064 26.885 62.712 ;
     RECT  26.675 60.384 26.957 61.08 ;
     RECT  26.677 31.776 26.993 33 ;
     RECT  26.993 31.776 27.025 32.52 ;
     RECT  26.627 39.36 27.101 49.512 ;
     RECT  26.809 19.2 27.137 19.272 ;
     RECT  25.585 29.808 27.301 29.832 ;
     RECT  26.377 71.232 27.308 71.88 ;
     RECT  26.291 34.752 27.313 38.28 ;
     RECT  26.701 55.488 27.317 59.256 ;
     RECT  26.773 21.936 27.34 25.752 ;
     RECT  26.093 68.88 27.349 68.904 ;
     RECT  27.101 43.92 27.389 49.512 ;
     RECT  27.308 70.896 27.389 71.88 ;
     RECT  27.389 70.896 27.395 71.256 ;
     RECT  27.349 68.88 27.433 69.528 ;
     RECT  26.627 50.592 27.493 54.216 ;
     RECT  27.317 55.488 27.493 57.144 ;
     RECT  26.777 14.976 27.497 15 ;
     RECT  27.34 25.152 27.529 25.752 ;
     RECT  26.197 26.736 27.529 27.672 ;
     RECT  27.137 19.2 27.569 19.224 ;
     RECT  27.025 30.96 27.601 32.52 ;
     RECT  26.885 62.064 27.605 62.088 ;
     RECT  27.529 25.152 27.673 27.672 ;
     RECT  27.673 25.152 27.713 28.488 ;
     RECT  27.301 29.664 27.745 29.832 ;
     RECT  27.713 25.248 27.749 28.488 ;
     RECT  26.771 65.808 27.781 66.792 ;
     RECT  27.389 46.032 27.889 49.512 ;
     RECT  27.493 50.592 27.889 57.144 ;
     RECT  27.433 68.88 27.889 68.904 ;
     RECT  27.749 26.784 27.925 28.488 ;
     RECT  27.745 29.616 27.925 29.832 ;
     RECT  27.781 65.472 27.929 66.792 ;
     RECT  27.749 25.248 27.965 25.608 ;
     RECT  27.317 58.512 27.965 59.256 ;
     RECT  27.457 64.416 27.965 64.44 ;
     RECT  27.601 30.912 28.109 32.52 ;
     RECT  27.889 46.032 28.109 57.144 ;
     RECT  27.313 34.176 28.177 38.28 ;
     RECT  27.101 39.36 28.177 42.888 ;
     RECT  27.889 68.448 28.181 68.904 ;
     RECT  27.929 65.664 28.253 66.792 ;
     RECT  27.389 43.92 28.393 45.048 ;
     RECT  28.109 46.032 28.393 49.56 ;
     RECT  27.965 58.512 28.393 59.208 ;
     RECT  28.105 19.872 28.429 19.992 ;
     RECT  28.177 34.176 28.501 42.888 ;
     RECT  27.997 15.264 28.537 15.288 ;
     RECT  28.609 62.736 28.645 62.76 ;
     RECT  28.109 32.496 28.681 32.52 ;
     RECT  28.501 33.6 28.681 42.888 ;
     RECT  28.429 19.872 28.861 20.904 ;
     RECT  27.34 21.936 28.861 24.024 ;
     RECT  27.965 25.248 28.861 25.512 ;
     RECT  27.925 26.784 28.885 29.832 ;
     RECT  28.681 32.496 28.933 42.888 ;
     RECT  28.393 43.92 28.933 49.56 ;
     RECT  26.476 13.296 29.077 13.608 ;
     RECT  28.537 14.64 29.077 15.864 ;
     RECT  28.109 30.912 29.077 31.464 ;
     RECT  28.933 32.496 29.077 49.56 ;
     RECT  28.393 58.128 29.113 59.208 ;
     RECT  26.957 61.056 29.113 61.08 ;
     RECT  28.645 62.256 29.113 62.76 ;
     RECT  29.077 30.912 29.149 49.56 ;
     RECT  28.109 50.592 29.149 57.144 ;
     RECT  29.149 30.912 29.185 57.144 ;
     RECT  28.253 65.664 29.221 66.12 ;
     RECT  29.077 67.632 29.221 67.656 ;
     RECT  28.885 26.736 29.269 29.832 ;
     RECT  29.185 30.864 29.269 57.144 ;
     RECT  29.221 65.664 29.329 67.656 ;
     RECT  28.969 68.976 29.329 69 ;
     RECT  29.269 26.592 29.401 57.144 ;
     RECT  29.113 58.128 29.401 59.304 ;
     RECT  25.765 3.84 29.408 3.864 ;
     RECT  29.077 13.296 29.408 16.056 ;
     RECT  28.501 17.664 29.408 17.688 ;
     RECT  28.861 19.872 29.408 20.952 ;
     RECT  28.861 21.936 29.408 25.512 ;
     RECT  29.401 26.592 29.408 59.304 ;
     RECT  29.113 61.056 29.408 62.76 ;
     RECT  28.321 63.84 29.408 63.864 ;
     RECT  29.329 65.664 29.408 69 ;
     RECT  29.408 2.148 29.512 84.252 ;
     RECT  29.512 2.418 29.704 83.982 ;
     RECT  29.704 68.208 29.729 69 ;
     RECT  29.704 53.232 29.765 63.864 ;
     RECT  29.704 65.664 29.765 66.36 ;
     RECT  29.704 14.64 29.837 14.856 ;
     RECT  29.704 22.08 29.837 23.16 ;
     RECT  29.704 17.664 29.873 18.216 ;
     RECT  29.765 53.232 29.945 63.816 ;
     RECT  29.704 24.384 29.98 38.52 ;
     RECT  29.704 41.376 29.981 43.08 ;
     RECT  29.704 13.296 30.017 13.608 ;
     RECT  29.837 22.08 30.053 23.064 ;
     RECT  29.704 46.368 30.089 50.424 ;
     RECT  29.945 53.232 30.125 61.608 ;
     RECT  29.98 32.496 30.197 38.52 ;
     RECT  30.197 32.496 30.227 34.488 ;
     RECT  30.197 35.52 30.233 38.52 ;
     RECT  30.089 46.368 30.413 49.608 ;
     RECT  30.125 53.232 30.419 60.456 ;
     RECT  30.419 55.2 30.521 60.456 ;
     RECT  29.729 68.208 30.521 68.376 ;
     RECT  29.837 14.832 30.593 14.856 ;
     RECT  30.227 32.832 30.593 33.336 ;
     RECT  30.053 22.08 30.629 22.776 ;
     RECT  30.521 55.248 30.665 60.456 ;
     RECT  30.665 55.248 30.707 59.304 ;
     RECT  29.98 24.384 30.737 31.464 ;
     RECT  30.593 32.832 30.737 33.048 ;
     RECT  29.704 19.872 30.769 20.952 ;
     RECT  29.945 62.832 30.769 63.816 ;
     RECT  30.769 19.776 30.773 20.952 ;
     RECT  30.707 55.392 30.773 59.304 ;
     RECT  30.737 24.384 30.805 25.56 ;
     RECT  30.413 46.368 30.809 48.168 ;
     RECT  30.125 61.536 30.809 61.608 ;
     RECT  29.704 39.552 30.812 40.392 ;
     RECT  29.981 41.376 30.812 43.032 ;
     RECT  29.704 44.16 30.841 44.184 ;
     RECT  30.227 34.464 30.845 34.488 ;
     RECT  30.233 35.616 30.853 38.52 ;
     RECT  30.737 28.992 30.917 31.464 ;
     RECT  30.812 39.552 30.917 43.032 ;
     RECT  29.704 16.032 30.989 16.056 ;
     RECT  30.841 44.112 30.989 44.184 ;
     RECT  30.773 55.392 30.989 58.968 ;
     RECT  30.521 68.256 31.025 68.376 ;
     RECT  30.769 62.832 31.061 63.864 ;
     RECT  30.413 49.584 31.129 49.608 ;
     RECT  30.805 24 31.169 25.56 ;
     RECT  30.665 60.432 31.169 60.456 ;
     RECT  30.809 61.536 31.205 61.56 ;
     RECT  30.853 35.616 31.237 38.568 ;
     RECT  30.917 39.552 31.237 40.872 ;
     RECT  30.989 55.392 31.241 58.824 ;
     RECT  30.773 20.928 31.309 20.952 ;
     RECT  30.629 22.08 31.309 22.344 ;
     RECT  30.989 44.16 31.309 44.184 ;
     RECT  31.237 34.368 31.345 34.44 ;
     RECT  29.704 52.032 31.381 52.056 ;
     RECT  30.917 42.432 31.385 43.032 ;
     RECT  31.061 62.832 31.385 62.856 ;
     RECT  30.917 29.664 31.417 31.464 ;
     RECT  30.737 32.832 31.417 33 ;
     RECT  30.419 53.232 31.417 53.88 ;
     RECT  31.129 49.584 31.427 50.568 ;
     RECT  31.241 55.392 31.457 58.728 ;
     RECT  31.427 50.112 31.468 50.136 ;
     RECT  29.873 18.192 31.489 18.216 ;
     RECT  29.765 65.664 31.525 65.976 ;
     RECT  31.201 15.984 31.561 16.008 ;
     RECT  31.381 51.6 31.561 52.056 ;
     RECT  31.237 35.616 31.565 40.872 ;
     RECT  31.561 51.6 31.597 52.104 ;
     RECT  31.417 53.088 31.597 53.88 ;
     RECT  31.561 15.84 31.601 16.008 ;
     RECT  31.345 34.272 31.633 34.44 ;
     RECT  31.597 51.6 31.669 53.88 ;
     RECT  31.525 65.664 31.669 66.072 ;
     RECT  31.489 17.616 31.705 18.216 ;
     RECT  30.773 19.776 31.705 19.896 ;
     RECT  31.705 17.616 31.763 19.896 ;
     RECT  31.669 64.896 31.781 66.072 ;
     RECT  31.763 18.816 31.789 19.896 ;
     RECT  31.169 24 31.813 25.512 ;
     RECT  31.789 19.776 31.817 19.896 ;
     RECT  31.385 42.432 31.817 42.84 ;
     RECT  31.309 44.16 31.817 44.424 ;
     RECT  31.061 63.84 31.849 63.864 ;
     RECT  30.017 13.296 31.859 13.32 ;
     RECT  31.309 20.928 31.859 22.344 ;
     RECT  31.633 34.224 31.889 34.44 ;
     RECT  31.565 35.616 31.889 40.488 ;
     RECT  31.889 36.24 31.907 40.488 ;
     RECT  31.813 23.952 31.961 25.512 ;
     RECT  31.417 29.664 31.993 33 ;
     RECT  31.817 42.432 32.033 42.744 ;
     RECT  31.781 65.664 32.101 66.072 ;
     RECT  31.859 20.928 32.137 20.952 ;
     RECT  31.669 51.6 32.173 54.312 ;
     RECT  32.173 51.456 32.177 54.312 ;
     RECT  31.817 44.4 32.209 44.424 ;
     RECT  31.453 62.688 32.281 62.712 ;
     RECT  30.737 26.64 32.317 27.768 ;
     RECT  30.809 46.368 32.317 48.12 ;
     RECT  32.281 61.584 32.389 62.712 ;
     RECT  31.849 63.84 32.389 64.584 ;
     RECT  31.993 29.664 32.396 33.048 ;
     RECT  31.457 55.392 32.425 57.864 ;
     RECT  31.907 36.336 32.429 40.488 ;
     RECT  32.317 46.368 32.429 49.08 ;
     RECT  32.101 65.664 32.437 66.936 ;
     RECT  31.025 68.256 32.437 68.28 ;
     RECT  32.396 28.992 32.483 33.048 ;
     RECT  32.437 65.664 32.483 68.28 ;
     RECT  31.859 22.08 32.497 22.344 ;
     RECT  32.389 61.584 32.501 64.584 ;
     RECT  32.245 60.096 32.533 60.12 ;
     RECT  32.177 52.512 32.573 54.312 ;
     RECT  32.425 55.296 32.641 57.864 ;
     RECT  32.533 60.096 32.641 60.408 ;
     RECT  32.501 61.584 32.717 63.336 ;
     RECT  32.501 64.368 32.749 64.584 ;
     RECT  32.483 65.664 32.749 67.704 ;
     RECT  32.573 52.512 32.753 53.88 ;
     RECT  32.033 42.624 32.785 42.744 ;
     RECT  32.137 20.112 32.821 20.952 ;
     RECT  32.497 22.08 32.821 22.488 ;
     RECT  32.753 52.512 32.825 53.64 ;
     RECT  32.749 64.368 32.897 67.704 ;
     RECT  31.601 15.84 32.965 15.864 ;
     RECT  31.889 34.224 32.993 34.392 ;
     RECT  32.965 15.84 33.005 16.008 ;
     RECT  32.785 42.624 33.061 43.176 ;
     RECT  32.483 29.136 33.073 33.048 ;
     RECT  32.993 34.224 33.073 35.352 ;
     RECT  33.073 29.136 33.077 35.352 ;
     RECT  32.209 44.4 33.077 45.192 ;
     RECT  32.897 64.368 33.077 66.936 ;
     RECT  32.821 20.112 33.149 22.488 ;
     RECT  32.717 62.736 33.149 63.336 ;
     RECT  32.429 40.176 33.157 40.488 ;
     RECT  33.061 42.192 33.157 43.176 ;
     RECT  32.177 51.456 33.157 51.48 ;
     RECT  32.825 52.512 33.157 53.592 ;
     RECT  33.077 64.368 33.185 64.584 ;
     RECT  31.763 17.616 33.217 17.64 ;
     RECT  33.077 29.136 33.221 34.488 ;
     RECT  32.317 25.776 33.253 27.768 ;
     RECT  32.429 36.336 33.253 38.616 ;
     RECT  32.717 61.584 33.253 61.608 ;
     RECT  33.157 51.456 33.257 53.592 ;
     RECT  32.533 50.16 33.26 50.184 ;
     RECT  33.257 51.456 33.26 51.912 ;
     RECT  33.077 44.448 33.361 45.192 ;
     RECT  32.429 46.368 33.361 48.12 ;
     RECT  33.157 40.176 33.365 43.176 ;
     RECT  33.149 20.688 33.401 22.488 ;
     RECT  33.221 30.576 33.401 34.488 ;
     RECT  33.077 65.616 33.443 66.936 ;
     RECT  33.185 64.368 33.481 64.488 ;
     RECT  32.641 55.296 33.493 58.776 ;
     RECT  32.641 59.856 33.493 60.408 ;
     RECT  33.005 15.984 33.505 16.008 ;
     RECT  33.401 20.928 33.541 22.488 ;
     RECT  31.961 23.952 33.541 24.504 ;
     RECT  33.505 15.984 33.577 16.584 ;
     RECT  33.365 40.176 33.577 42.744 ;
     RECT  33.493 55.296 33.635 60.408 ;
     RECT  33.253 25.632 33.637 27.768 ;
     RECT  33.221 29.136 33.637 29.496 ;
     RECT  33.481 64.464 33.653 64.488 ;
     RECT  33.637 25.632 33.683 29.496 ;
     RECT  33.577 15.984 33.685 16.632 ;
     RECT  33.217 17.616 33.685 17.784 ;
     RECT  33.26 50.16 33.685 51.912 ;
     RECT  33.683 25.632 33.761 27.432 ;
     RECT  33.149 62.736 33.761 62.76 ;
     RECT  33.253 61.488 33.793 61.608 ;
     RECT  33.685 15.984 33.829 17.784 ;
     RECT  33.829 15.984 33.901 18.552 ;
     RECT  33.361 44.448 33.973 48.12 ;
     RECT  33.635 55.488 34.117 60.408 ;
     RECT  33.793 61.488 34.117 62.616 ;
     RECT  33.683 28.416 34.225 29.496 ;
     RECT  33.401 30.576 34.225 32.328 ;
     RECT  33.973 44.448 34.297 48.744 ;
     RECT  33.685 49.776 34.297 51.912 ;
     RECT  34.297 44.448 34.441 51.912 ;
     RECT  33.901 15.984 34.597 18.84 ;
     RECT  33.401 33.552 34.657 34.488 ;
     RECT  34.225 28.416 34.693 32.328 ;
     RECT  34.657 33.552 34.693 35.208 ;
     RECT  33.443 65.616 34.729 66.744 ;
     RECT  33.761 25.776 34.765 25.8 ;
     RECT  33.761 27.12 34.765 27.432 ;
     RECT  29.704 3.84 34.808 3.864 ;
     RECT  34.597 15.456 34.808 18.84 ;
     RECT  33.541 20.928 34.808 24.504 ;
     RECT  34.765 25.776 34.808 27.432 ;
     RECT  34.693 28.416 34.808 35.208 ;
     RECT  33.253 36.24 34.808 38.616 ;
     RECT  33.577 39.792 34.808 42.744 ;
     RECT  34.441 44.448 34.808 52.2 ;
     RECT  33.257 53.328 34.808 53.592 ;
     RECT  34.117 55.488 34.808 62.616 ;
     RECT  34.729 64.992 34.808 66.744 ;
     RECT  34.165 82.224 34.808 82.248 ;
     RECT  34.808 2.148 34.912 84.252 ;
     RECT  34.912 2.418 35.104 83.982 ;
     RECT  35.104 54.672 35.165 55.992 ;
     RECT  35.104 16.56 35.219 18.936 ;
     RECT  35.104 20.496 35.219 29.352 ;
     RECT  35.219 20.496 35.267 24.168 ;
     RECT  35.219 25.344 35.267 29.352 ;
     RECT  35.104 30.432 35.267 33.624 ;
     RECT  35.267 20.496 35.345 24.072 ;
     RECT  35.104 43.296 35.345 50.04 ;
     RECT  35.345 43.296 35.381 49.08 ;
     RECT  35.345 20.544 35.453 24.072 ;
     RECT  35.381 46.224 35.453 49.08 ;
     RECT  35.104 35.184 35.489 38.376 ;
     RECT  35.104 39.36 35.489 41.64 ;
     RECT  35.267 30.624 35.561 33.624 ;
     RECT  35.104 57.84 35.597 60.984 ;
     RECT  35.489 37.584 35.633 38.376 ;
     RECT  35.489 40.32 35.633 41.64 ;
     RECT  35.381 43.296 35.705 45 ;
     RECT  35.104 63.552 35.741 66.264 ;
     RECT  35.453 20.544 35.957 22.92 ;
     RECT  35.597 60.672 35.993 60.984 ;
     RECT  35.165 54.672 36.029 55.944 ;
     RECT  35.993 60.816 36.029 60.984 ;
     RECT  35.597 57.84 36.137 59.592 ;
     RECT  35.741 63.552 36.173 66.168 ;
     RECT  35.705 43.296 36.181 43.32 ;
     RECT  36.181 42.864 36.205 43.32 ;
     RECT  35.104 51.12 36.241 53.688 ;
     RECT  35.489 35.184 36.277 36.6 ;
     RECT  36.137 57.84 36.289 58.728 ;
     RECT  35.267 29.232 36.313 29.352 ;
     RECT  35.561 30.624 36.313 32.472 ;
     RECT  35.561 33.6 36.323 33.624 ;
     RECT  36.277 34.896 36.353 36.6 ;
     RECT  35.453 46.224 36.353 48.84 ;
     RECT  36.353 34.896 36.364 34.92 ;
     RECT  36.173 65.376 36.371 66.168 ;
     RECT  36.371 65.376 36.412 65.976 ;
     RECT  36.241 50.16 36.425 53.688 ;
     RECT  36.289 57.84 36.425 58.488 ;
     RECT  36.029 60.96 36.457 60.984 ;
     RECT  35.219 18.768 36.493 18.936 ;
     RECT  36.029 55.488 36.493 55.944 ;
     RECT  35.633 40.32 36.515 41.064 ;
     RECT  36.353 35.904 36.533 36.6 ;
     RECT  36.173 63.552 36.533 64.392 ;
     RECT  36.425 50.16 36.569 53.4 ;
     RECT  36.493 49.008 36.601 49.032 ;
     RECT  36.515 40.416 36.641 41.064 ;
     RECT  36.601 49.008 36.641 49.128 ;
     RECT  36.205 42.72 36.745 43.32 ;
     RECT  35.957 20.592 36.749 22.92 ;
     RECT  35.219 16.56 36.781 17.688 ;
     RECT  36.493 18.768 36.781 19.176 ;
     RECT  36.457 60.96 36.821 61.56 ;
     RECT  36.313 29.232 36.857 32.472 ;
     RECT  36.641 49.104 36.857 49.128 ;
     RECT  35.104 15.168 36.86 15.48 ;
     RECT  36.781 16.56 36.86 19.176 ;
     RECT  36.749 22.224 36.893 22.92 ;
     RECT  35.267 25.344 36.893 27.96 ;
     RECT  36.857 29.232 36.893 29.304 ;
     RECT  36.86 15.168 36.929 19.176 ;
     RECT  36.569 51.168 36.947 53.4 ;
     RECT  36.821 60.96 36.947 61.368 ;
     RECT  36.533 63.552 36.961 63.864 ;
     RECT  36.947 51.888 36.965 53.4 ;
     RECT  36.929 15.168 37.001 17.928 ;
     RECT  36.961 63.216 37.001 63.864 ;
     RECT  36.493 55.488 37.007 56.424 ;
     RECT  35.705 44.448 37.037 45 ;
     RECT  36.893 25.344 37.043 27.672 ;
     RECT  37.007 55.488 37.045 57.336 ;
     RECT  36.947 60.96 37.045 61.032 ;
     RECT  37.045 55.008 37.069 57.336 ;
     RECT  37.043 25.728 37.073 27.672 ;
     RECT  37.069 54.72 37.091 57.336 ;
     RECT  37.045 60.384 37.091 61.032 ;
     RECT  37.091 54.72 37.093 55.8 ;
     RECT  37.001 16.224 37.109 17.928 ;
     RECT  37.093 54.384 37.132 55.8 ;
     RECT  36.641 40.416 37.145 40.44 ;
     RECT  37.132 54.384 37.153 54.744 ;
     RECT  35.633 37.584 37.244 38.28 ;
     RECT  36.533 35.904 37.331 36.264 ;
     RECT  37.244 37.248 37.331 38.28 ;
     RECT  36.425 58.464 37.333 58.488 ;
     RECT  37.091 60.384 37.333 60.408 ;
     RECT  37.091 57.312 37.379 57.336 ;
     RECT  37.333 58.464 37.397 60.408 ;
     RECT  37.397 58.464 37.42 59.448 ;
     RECT  37.42 58.464 37.429 58.728 ;
     RECT  37.001 63.216 37.433 63.24 ;
     RECT  36.569 50.16 37.541 50.184 ;
     RECT  37.037 44.976 37.58 45 ;
     RECT  36.353 46.224 37.58 47.64 ;
     RECT  36.745 42.192 37.613 43.32 ;
     RECT  37.58 44.976 37.667 47.64 ;
     RECT  36.749 20.592 37.681 21.144 ;
     RECT  36.857 30.816 37.681 32.472 ;
     RECT  37.681 30.816 37.793 33.384 ;
     RECT  36.412 65.952 37.811 65.976 ;
     RECT  37.109 16.224 37.829 16.872 ;
     RECT  36.929 19.152 37.852 19.176 ;
     RECT  37.001 15.168 37.865 15.192 ;
     RECT  37.613 42.336 37.901 43.32 ;
     RECT  37.285 29.04 38.009 29.064 ;
     RECT  37.109 17.904 38.041 17.928 ;
     RECT  35.453 24.048 38.041 24.072 ;
     RECT  37.829 16.464 38.081 16.872 ;
     RECT  37.793 30.816 38.081 32.472 ;
     RECT  38.041 24.048 38.113 24.792 ;
     RECT  37.073 25.776 38.113 27.672 ;
     RECT  37.153 54.384 38.149 54.408 ;
     RECT  37.132 55.776 38.149 55.8 ;
     RECT  36.965 51.936 38.153 53.4 ;
     RECT  37.429 58.32 38.195 58.728 ;
     RECT  38.113 24.048 38.221 27.672 ;
     RECT  37.667 46.752 38.245 47.64 ;
     RECT  38.245 46.752 38.261 48.456 ;
     RECT  37.331 37.584 38.329 38.28 ;
     RECT  38.252 29.616 38.339 29.64 ;
     RECT  38.081 31.008 38.341 32.472 ;
     RECT  38.221 24.048 38.513 28.344 ;
     RECT  38.261 47.376 38.513 48.456 ;
     RECT  38.329 37.104 38.657 38.28 ;
     RECT  37.901 42.624 38.765 43.32 ;
     RECT  38.149 54.384 38.773 55.8 ;
     RECT  38.195 58.32 38.773 58.344 ;
     RECT  38.341 31.92 38.801 32.472 ;
     RECT  38.773 54.144 38.819 55.8 ;
     RECT  38.773 58.128 38.819 58.344 ;
     RECT  38.657 37.104 38.833 37.128 ;
     RECT  38.041 17.904 38.905 18.12 ;
     RECT  38.513 24.048 38.905 24.12 ;
     RECT  38.513 25.104 38.909 28.344 ;
     RECT  38.801 31.92 38.909 31.944 ;
     RECT  38.765 42.72 38.909 43.32 ;
     RECT  38.833 36.912 38.981 37.128 ;
     RECT  38.204 49.968 39.013 49.992 ;
     RECT  38.981 36.912 39.053 36.936 ;
     RECT  38.153 51.936 39.059 52.488 ;
     RECT  38.819 55.152 39.059 55.8 ;
     RECT  37.681 20.208 39.085 21.144 ;
     RECT  38.657 38.112 39.121 38.28 ;
     RECT  38.909 28.32 39.161 28.344 ;
     RECT  38.909 43.056 39.161 43.32 ;
     RECT  39.121 38.112 39.203 39.384 ;
     RECT  37.331 35.904 39.205 35.928 ;
     RECT  39.203 38.256 39.205 39.384 ;
     RECT  39.085 19.968 39.229 21.144 ;
     RECT  36.893 22.224 39.229 22.248 ;
     RECT  39.205 35.28 39.229 35.928 ;
     RECT  39.229 34.8 39.253 35.928 ;
     RECT  39.229 19.968 39.265 22.248 ;
     RECT  38.905 23.664 39.265 24.12 ;
     RECT  39.013 49.968 39.493 50.28 ;
     RECT  39.301 51.456 39.493 51.48 ;
     RECT  38.081 16.464 39.541 16.488 ;
     RECT  38.905 17.904 39.541 18.744 ;
     RECT  39.265 19.968 39.541 24.12 ;
     RECT  35.104 3.84 40.208 3.864 ;
     RECT  39.541 16.464 40.208 24.12 ;
     RECT  38.909 25.104 40.208 27.144 ;
     RECT  39.253 34.176 40.208 35.928 ;
     RECT  39.205 38.256 40.208 38.808 ;
     RECT  39.161 43.056 40.208 43.08 ;
     RECT  38.513 47.376 40.208 47.64 ;
     RECT  39.493 49.968 40.208 51.48 ;
     RECT  39.059 52.464 40.208 52.488 ;
     RECT  38.819 54.144 40.208 54.168 ;
     RECT  39.059 55.776 40.208 55.8 ;
     RECT  38.819 58.128 40.208 58.152 ;
     RECT  35.104 82.128 40.208 82.152 ;
     RECT  40.208 2.148 40.312 84.252 ;
     RECT  40.312 2.418 40.504 83.982 ;
     RECT  40.504 57.984 40.601 58.152 ;
     RECT  40.504 42.816 41.609 43.08 ;
     RECT  40.504 3.84 45.608 3.864 ;
     RECT  40.504 38.256 45.608 38.28 ;
     RECT  41.609 42.816 45.608 42.84 ;
     RECT  40.504 47.616 45.608 47.64 ;
     RECT  40.504 55.776 45.608 55.8 ;
     RECT  40.601 57.984 45.608 58.008 ;
     RECT  40.504 82.128 45.608 82.152 ;
     RECT  45.608 2.148 45.712 84.252 ;
     RECT  45.712 2.418 45.904 83.982 ;
     RECT  45.904 3.84 51.008 3.864 ;
     RECT  45.904 38.256 51.008 38.28 ;
     RECT  45.904 42.816 51.008 42.84 ;
     RECT  45.904 47.616 51.008 47.64 ;
     RECT  45.904 55.776 51.008 55.8 ;
     RECT  45.904 57.984 51.008 58.008 ;
     RECT  45.904 82.128 51.008 82.152 ;
     RECT  51.008 2.148 51.112 84.252 ;
     RECT  51.112 2.418 51.304 83.982 ;
     RECT  51.304 82.128 54.709 82.152 ;
     RECT  54.709 82.128 54.749 82.248 ;
     RECT  51.304 3.84 56.408 3.864 ;
     RECT  51.304 38.256 56.408 38.28 ;
     RECT  51.304 42.816 56.408 42.84 ;
     RECT  51.304 47.616 56.408 47.64 ;
     RECT  51.304 55.776 56.408 55.8 ;
     RECT  51.304 57.984 56.408 58.008 ;
     RECT  54.749 82.224 56.408 82.248 ;
     RECT  56.408 2.148 56.512 84.252 ;
     RECT  56.512 2.418 56.704 83.982 ;
     RECT  56.704 82.224 57.805 82.248 ;
     RECT  57.805 82.224 58.745 82.68 ;
     RECT  58.489 85.488 58.769 85.512 ;
     RECT  56.704 38.256 58.781 38.28 ;
     RECT  58.745 82.224 58.885 82.248 ;
     RECT  56.704 55.776 58.988 55.8 ;
     RECT  58.885 81.984 59.029 82.248 ;
     RECT  58.988 55.776 59.075 55.848 ;
     RECT  59.029 81.504 59.177 82.248 ;
     RECT  59.075 55.776 59.285 55.8 ;
     RECT  58.769 85.488 59.356 86.28 ;
     RECT  59.356 85.584 59.411 86.28 ;
     RECT  59.177 81.984 59.465 82.248 ;
     RECT  59.411 86.256 59.465 86.28 ;
     RECT  58.885 84.336 59.573 84.36 ;
     RECT  59.465 81.984 59.861 82.008 ;
     RECT  56.704 3.84 61.808 3.864 ;
     RECT  56.704 42.816 61.808 42.84 ;
     RECT  56.704 47.616 61.808 47.64 ;
     RECT  56.704 57.984 61.808 58.008 ;
     RECT  61.808 2.148 61.912 84.252 ;
     RECT  61.912 2.418 62.104 83.982 ;
     RECT  66.469 1.728 66.701 1.752 ;
     RECT  62.104 3.84 67.208 3.864 ;
     RECT  62.104 42.816 67.208 42.84 ;
     RECT  62.104 47.616 67.208 47.64 ;
     RECT  62.104 57.984 67.208 58.008 ;
     RECT  67.208 2.148 67.312 84.252 ;
     RECT  67.312 2.418 67.504 83.982 ;
     RECT  67.504 3.84 67.925 3.864 ;
     RECT  67.504 47.616 72.608 47.64 ;
     RECT  67.504 57.984 72.608 58.008 ;
     RECT  72.608 2.148 72.712 84.252 ;
     RECT  72.712 2.418 72.904 83.982 ;
     RECT  72.904 57.984 76.705 58.008 ;
     RECT  76.705 57.552 77.929 58.008 ;
     RECT  72.904 47.616 78.008 47.64 ;
     RECT  77.929 57.408 78.008 58.008 ;
     RECT  78.008 2.148 78.112 84.252 ;
     RECT  78.112 2.418 78.304 83.982 ;
     RECT  78.304 57.408 79.337 57.432 ;
     RECT  80.629 58.128 81.713 58.152 ;
     RECT  78.304 47.616 81.857 47.64 ;
     RECT  83.408 2.148 83.512 84.252 ;
     RECT  83.512 2.418 83.704 83.982 ;
     RECT  85.453 57.936 86.281 58.056 ;
     RECT  86.281 57.84 86.364 58.056 ;
    LAYER M5 ;
     RECT  66.384 0.016 66.504 2.137 ;
     RECT  2.4 2.137 2.52 2.151 ;
     RECT  7.8 2.137 7.92 2.151 ;
     RECT  13.2 2.137 13.32 2.151 ;
     RECT  18.6 2.137 18.72 2.151 ;
     RECT  24 2.137 24.12 2.151 ;
     RECT  29.4 2.137 29.52 2.151 ;
     RECT  34.8 2.137 34.92 2.151 ;
     RECT  40.2 2.137 40.32 2.151 ;
     RECT  45.6 2.137 45.72 2.151 ;
     RECT  51 2.137 51.12 2.151 ;
     RECT  56.4 2.137 56.52 2.151 ;
     RECT  61.8 2.137 61.92 2.151 ;
     RECT  66.384 2.137 67.32 2.151 ;
     RECT  72.6 2.137 72.72 2.151 ;
     RECT  78 2.137 78.12 2.151 ;
     RECT  83.4 2.137 83.52 2.151 ;
     RECT  24 2.151 24.312 8.821 ;
     RECT  13.2 2.151 13.512 9.061 ;
     RECT  16.512 8.485 16.536 9.301 ;
     RECT  13.2 9.061 14.136 9.827 ;
     RECT  15.984 9.301 16.536 9.875 ;
     RECT  11.856 9.637 11.88 9.925 ;
     RECT  11.424 9.925 11.88 9.971 ;
     RECT  20.208 8.437 20.232 9.971 ;
     RECT  18.6 2.151 18.912 10.789 ;
     RECT  23.376 8.821 24.312 10.931 ;
     RECT  7.8 2.151 8.112 11.029 ;
     RECT  11.424 9.971 11.448 11.171 ;
     RECT  7.392 11.029 8.112 11.269 ;
     RECT  13.2 9.827 13.512 11.941 ;
     RECT  16.512 9.875 16.536 12.517 ;
     RECT  25.776 3.829 25.8 12.517 ;
     RECT  12.528 11.941 13.512 12.995 ;
     RECT  7.392 11.269 9.048 13.093 ;
     RECT  15.792 12.517 16.536 13.093 ;
     RECT  7.392 13.093 9.144 13.139 ;
     RECT  7.68 13.139 9.144 13.235 ;
     RECT  14.976 13.093 16.536 13.235 ;
     RECT  13.2 12.995 13.512 13.573 ;
     RECT  7.68 13.235 9.048 13.619 ;
     RECT  15.216 13.235 16.536 13.619 ;
     RECT  25.44 12.517 25.8 13.619 ;
     RECT  24 10.931 24.312 13.621 ;
     RECT  24 13.621 24.456 13.813 ;
     RECT  15.216 13.619 15.816 14.243 ;
     RECT  11.136 11.365 11.16 14.245 ;
     RECT  10.992 14.245 11.16 14.485 ;
     RECT  18.6 10.789 19.512 14.677 ;
     RECT  13.2 13.573 13.704 14.867 ;
     RECT  18.24 14.677 19.512 14.963 ;
     RECT  26.4 13.909 26.424 15.011 ;
     RECT  7.68 13.619 8.112 15.301 ;
     RECT  9.648 15.301 9.672 15.443 ;
     RECT  10.992 14.485 11.688 15.443 ;
     RECT  34.8 2.151 35.112 15.445 ;
     RECT  15.648 14.243 15.816 15.589 ;
     RECT  18.24 14.963 18.912 15.829 ;
     RECT  20.496 15.205 20.52 16.117 ;
     RECT  24 13.813 24.984 16.357 ;
     RECT  13.2 14.867 13.512 16.405 ;
     RECT  20.496 16.117 20.76 16.405 ;
     RECT  23.664 16.357 24.984 16.501 ;
     RECT  7.68 15.301 8.376 16.595 ;
     RECT  5.184 15.877 5.208 16.691 ;
     RECT  20.304 16.405 20.76 16.931 ;
     RECT  40.2 2.151 40.512 17.029 ;
     RECT  7.68 16.595 8.328 17.171 ;
     RECT  15.648 15.589 16.296 17.171 ;
     RECT  17.76 15.829 18.912 17.171 ;
     RECT  13.2 16.405 14.232 17.651 ;
     RECT  10.992 15.443 11.16 17.699 ;
     RECT  36.912 15.157 36.936 17.747 ;
     RECT  34.608 15.445 35.112 17.989 ;
     RECT  10.992 17.699 11.016 18.131 ;
     RECT  31.824 13.285 31.848 18.181 ;
     RECT  13.2 17.651 13.704 18.803 ;
     RECT  15.648 17.171 15.672 18.851 ;
     RECT  18.24 17.171 18.912 18.851 ;
     RECT  31.728 18.181 31.848 18.851 ;
     RECT  20.304 16.931 20.328 19.285 ;
     RECT  2.4 2.151 2.712 19.333 ;
     RECT  7.68 17.171 8.112 19.333 ;
     RECT  21.888 19.381 21.912 19.573 ;
     RECT  23.664 16.501 25.032 19.573 ;
     RECT  31.824 18.851 31.848 19.813 ;
     RECT  18.6 18.851 18.912 20.053 ;
     RECT  13.2 18.803 13.512 20.101 ;
     RECT  7.344 19.333 8.112 20.147 ;
     RECT  19.968 19.285 20.328 20.195 ;
     RECT  37.776 19.141 37.8 20.243 ;
     RECT  19.968 20.195 19.992 20.387 ;
     RECT  17.808 20.053 18.912 20.435 ;
     RECT  7.68 20.147 8.112 20.437 ;
     RECT  9.12 17.941 9.144 20.437 ;
     RECT  34.608 17.989 35.208 20.485 ;
     RECT  5.136 18.757 5.16 20.579 ;
     RECT  10.848 19.909 10.872 20.579 ;
     RECT  21.888 19.573 25.032 20.723 ;
     RECT  29.4 2.151 29.712 20.917 ;
     RECT  2.4 19.333 3.432 21.107 ;
     RECT  34.608 20.485 35.304 21.109 ;
     RECT  31.632 19.813 31.848 21.445 ;
     RECT  7.68 20.437 9.144 21.493 ;
     RECT  34.608 21.109 35.352 21.539 ;
     RECT  13.2 20.101 13.608 21.733 ;
     RECT  29.088 20.917 29.712 21.925 ;
     RECT  39.552 17.029 40.512 21.971 ;
     RECT  28.224 21.925 29.712 22.067 ;
     RECT  6.864 21.493 9.144 22.643 ;
     RECT  2.4 21.107 2.856 22.741 ;
     RECT  15.552 22.165 15.96 22.789 ;
     RECT  9.12 22.643 9.144 22.835 ;
     RECT  14.784 22.789 15.96 22.835 ;
     RECT  24 20.723 25.032 22.835 ;
     RECT  13.2 21.733 13.656 23.029 ;
     RECT  14.784 22.835 15.576 23.029 ;
     RECT  13.2 23.029 15.576 23.267 ;
     RECT  24 22.835 24.552 23.315 ;
     RECT  14.784 23.267 15.576 23.363 ;
     RECT  18.336 20.435 18.912 23.461 ;
     RECT  21.888 20.723 22.776 23.605 ;
     RECT  21.648 23.605 22.776 23.651 ;
     RECT  17.424 23.461 18.912 23.795 ;
     RECT  13.2 23.267 13.608 23.893 ;
     RECT  40.08 21.971 40.512 23.893 ;
     RECT  31.536 21.445 31.848 23.987 ;
     RECT  21.648 23.651 21.672 24.131 ;
     RECT  34.8 21.539 35.208 24.133 ;
     RECT  0.144 22.789 0.168 24.467 ;
     RECT  2.4 22.741 3.528 24.469 ;
     RECT  4.56 24.325 4.584 24.469 ;
     RECT  17.952 23.795 18.912 24.469 ;
     RECT  22.752 23.651 22.776 24.563 ;
     RECT  26.784 23.845 26.808 24.757 ;
     RECT  14.928 23.363 15.576 24.947 ;
     RECT  21.024 24.853 21.048 25.043 ;
     RECT  24 23.315 24.312 25.045 ;
     RECT  39.36 23.893 40.512 25.139 ;
     RECT  29.088 22.067 29.712 25.189 ;
     RECT  31.536 23.987 31.56 25.381 ;
     RECT  15.552 24.947 15.576 25.429 ;
     RECT  17.952 24.469 19.704 25.475 ;
     RECT  30.816 25.381 31.56 25.523 ;
     RECT  34.8 24.133 35.256 25.669 ;
     RECT  6.864 22.643 8.112 25.715 ;
     RECT  12.624 23.893 13.608 25.715 ;
     RECT  26.784 24.757 27.288 25.717 ;
     RECT  15.552 25.429 16.488 25.763 ;
     RECT  26.784 25.717 27.336 25.763 ;
     RECT  6.912 25.715 8.112 25.811 ;
     RECT  34.8 25.669 35.304 25.955 ;
     RECT  2.4 24.469 4.584 26.149 ;
     RECT  7.488 25.811 8.112 26.485 ;
     RECT  13.056 25.715 13.608 26.485 ;
     RECT  16.272 25.763 16.488 26.677 ;
     RECT  10.512 25.045 10.536 26.725 ;
     RECT  29.088 25.189 29.832 26.725 ;
     RECT  37.008 25.333 37.032 26.725 ;
     RECT  36.48 26.725 37.032 26.771 ;
     RECT  22.752 25.861 22.776 26.819 ;
     RECT  34.8 25.955 35.256 26.915 ;
     RECT  2.4 26.149 5.544 27.059 ;
     RECT  18.336 25.475 19.704 27.059 ;
     RECT  28.896 26.725 29.832 27.157 ;
     RECT  20.736 26.149 20.76 27.299 ;
     RECT  27.264 25.763 27.336 27.347 ;
     RECT  10.512 26.725 10.776 27.395 ;
     RECT  24 25.045 24.456 27.781 ;
     RECT  7.488 26.485 8.568 27.827 ;
     RECT  3.696 27.059 5.544 27.829 ;
     RECT  7.68 27.827 8.568 27.923 ;
     RECT  16.272 26.677 17.304 27.971 ;
     RECT  36.48 26.771 36.504 27.971 ;
     RECT  3.696 27.829 6.264 28.115 ;
     RECT  13.056 26.485 13.656 28.163 ;
     RECT  33.648 26.725 33.672 28.451 ;
     RECT  16.272 27.971 16.344 28.453 ;
     RECT  24 27.781 25.128 28.499 ;
     RECT  3.696 28.115 4.632 28.643 ;
     RECT  34.8 26.915 35.208 28.741 ;
     RECT  31.536 25.523 31.56 28.981 ;
     RECT  7.68 27.923 8.112 29.029 ;
     RECT  34.8 28.741 35.256 29.029 ;
     RECT  28.896 27.157 30.456 29.123 ;
     RECT  10.56 27.395 10.776 29.125 ;
     RECT  11.952 27.877 11.976 29.125 ;
     RECT  29.088 29.123 30.456 29.171 ;
     RECT  34.272 29.029 35.256 29.267 ;
     RECT  4.512 28.643 4.632 29.363 ;
     RECT  10.56 29.125 11.976 29.411 ;
     RECT  4.56 29.363 4.632 29.413 ;
     RECT  4.56 29.413 4.728 29.459 ;
     RECT  15.792 28.453 16.344 29.459 ;
     RECT  24 28.499 24.312 29.605 ;
     RECT  31.536 28.981 32.472 29.653 ;
     RECT  6.24 28.115 6.264 29.699 ;
     RECT  27.312 27.347 27.336 29.699 ;
     RECT  31.536 29.653 33.096 29.699 ;
     RECT  18.432 27.059 19.704 29.795 ;
     RECT  15.84 29.459 16.344 29.939 ;
     RECT  10.56 29.411 10.776 30.275 ;
     RECT  11.952 29.411 11.976 30.421 ;
     RECT  13.056 28.163 13.608 30.421 ;
     RECT  34.8 29.267 35.256 30.467 ;
     RECT  15.936 29.939 16.344 30.613 ;
     RECT  15.936 30.613 16.584 30.659 ;
     RECT  11.952 30.421 13.608 30.803 ;
     RECT  18.48 29.795 19.704 30.997 ;
     RECT  38.304 28.309 38.328 31.043 ;
     RECT  29.088 29.171 30.264 31.139 ;
     RECT  34.8 30.467 35.208 31.141 ;
     RECT  12.768 30.803 13.608 31.235 ;
     RECT  2.4 27.059 2.712 31.285 ;
     RECT  31.536 29.699 31.56 31.333 ;
     RECT  33.072 29.699 33.096 31.333 ;
     RECT  4.608 29.459 4.728 31.379 ;
     RECT  16.272 30.659 16.584 31.427 ;
     RECT  4.704 31.379 4.728 31.955 ;
     RECT  7.44 29.029 8.112 31.955 ;
     RECT  12.768 31.235 13.512 31.955 ;
     RECT  16.272 31.427 16.344 32.243 ;
     RECT  6.288 31.285 6.312 32.339 ;
     RECT  31.536 31.333 33.096 32.339 ;
     RECT  34.368 31.141 35.208 32.339 ;
     RECT  7.68 31.955 8.112 32.437 ;
     RECT  16.272 32.243 16.296 32.437 ;
     RECT  36.384 31.237 36.408 32.483 ;
     RECT  38.256 31.525 38.28 32.483 ;
     RECT  29.088 31.139 29.928 32.485 ;
     RECT  2.4 31.285 2.808 33.011 ;
     RECT  4.512 32.437 4.536 33.011 ;
     RECT  23.424 29.605 24.312 33.011 ;
     RECT  31.536 32.339 32.232 33.011 ;
     RECT  34.704 32.339 35.208 33.061 ;
     RECT  10.56 30.275 10.584 33.155 ;
     RECT  34.704 33.061 35.304 33.155 ;
     RECT  17.952 30.997 19.704 33.683 ;
     RECT  13.2 31.955 13.512 33.877 ;
     RECT  13.2 33.877 13.608 34.165 ;
     RECT  24 33.011 24.312 34.165 ;
     RECT  40.2 25.139 40.512 34.165 ;
     RECT  7.68 32.437 8.616 34.213 ;
     RECT  18.6 33.683 19.704 34.213 ;
     RECT  29.088 32.485 30.216 34.259 ;
     RECT  5.664 33.013 5.688 34.309 ;
     RECT  5.376 34.309 5.688 34.355 ;
     RECT  7.392 34.213 8.616 34.403 ;
     RECT  7.392 34.403 8.112 34.451 ;
     RECT  26.64 33.013 26.664 34.501 ;
     RECT  36.288 33.589 36.312 34.931 ;
     RECT  24 34.165 25.08 35.171 ;
     RECT  13.2 34.165 13.656 35.267 ;
     RECT  39.264 34.165 40.512 35.269 ;
     RECT  26.256 34.501 26.664 35.363 ;
     RECT  34.8 33.155 35.304 35.413 ;
     RECT  5.376 34.355 5.4 35.651 ;
     RECT  29.088 34.259 29.928 35.795 ;
     RECT  6.672 35.077 6.696 35.845 ;
     RECT  7.68 34.451 8.112 35.845 ;
     RECT  31.536 33.011 31.56 35.845 ;
     RECT  2.4 33.011 2.712 35.893 ;
     RECT  3.984 34.645 4.008 35.893 ;
     RECT  13.2 35.267 13.608 35.893 ;
     RECT  2.4 35.893 4.008 35.939 ;
     RECT  39.216 35.269 40.512 35.939 ;
     RECT  16.08 32.437 16.296 36.085 ;
     RECT  30.816 35.845 31.56 36.229 ;
     RECT  30.816 36.229 31.896 36.275 ;
     RECT  28.08 35.029 28.104 36.325 ;
     RECT  29.088 35.795 29.712 36.325 ;
     RECT  34.8 35.413 35.928 36.325 ;
     RECT  12.864 35.893 13.608 36.371 ;
     RECT  31.872 36.275 31.896 36.371 ;
     RECT  28.08 36.325 29.712 36.515 ;
     RECT  6.672 35.845 8.112 36.803 ;
     RECT  10.56 34.117 10.584 37.091 ;
     RECT  18.6 34.213 19.944 37.091 ;
     RECT  26.64 35.363 26.664 37.091 ;
     RECT  37.296 35.893 37.32 37.283 ;
     RECT  33.024 35.317 33.048 37.429 ;
     RECT  34.8 36.325 36.216 37.429 ;
     RECT  33.024 37.429 36.216 37.475 ;
     RECT  29.232 36.515 29.712 37.573 ;
     RECT  6.72 36.803 8.112 37.619 ;
     RECT  33.984 37.475 36.216 37.619 ;
     RECT  30.816 36.275 30.84 37.715 ;
     RECT  29.184 37.573 29.712 37.763 ;
     RECT  28.08 36.515 28.104 38.149 ;
     RECT  2.4 35.939 3.144 38.195 ;
     RECT  33.984 37.619 35.112 38.387 ;
     RECT  16.08 36.085 16.872 38.725 ;
     RECT  2.4 38.195 3.096 38.819 ;
     RECT  15.936 38.725 16.872 38.867 ;
     RECT  12.864 36.371 13.512 39.013 ;
     RECT  5.424 37.573 5.448 39.251 ;
     RECT  24 35.171 24.6 39.253 ;
     RECT  21.744 35.845 21.768 39.395 ;
     RECT  39.168 38.101 39.192 39.395 ;
     RECT  10.512 38.581 10.536 39.539 ;
     RECT  29.28 37.763 29.712 39.589 ;
     RECT  12.528 39.013 13.512 39.781 ;
     RECT  14.544 38.773 14.568 39.781 ;
     RECT  12.528 39.781 14.568 39.827 ;
     RECT  18.6 37.091 19.704 39.875 ;
     RECT  18.6 39.875 18.912 39.877 ;
     RECT  34.368 38.387 35.112 39.923 ;
     RECT  20.688 38.581 20.712 40.165 ;
     RECT  36.192 37.619 36.216 40.309 ;
     RECT  16.08 38.867 16.872 40.453 ;
     RECT  18 39.877 18.912 40.453 ;
     RECT  27.696 38.149 28.104 40.547 ;
     RECT  24 39.253 25.224 40.885 ;
     RECT  2.4 38.819 2.808 40.981 ;
     RECT  23.904 40.885 25.224 40.981 ;
     RECT  23.904 40.981 25.272 41.027 ;
     RECT  7.632 37.619 8.112 41.075 ;
     RECT  12.528 39.827 14.376 41.075 ;
     RECT  30.864 38.533 30.888 41.075 ;
     RECT  36.192 40.309 36.504 41.075 ;
     RECT  3.984 40.741 4.008 41.461 ;
     RECT  19.968 40.165 20.712 41.605 ;
     RECT  10.176 39.877 10.2 41.651 ;
     RECT  19.968 41.605 21.096 41.651 ;
     RECT  33.168 40.165 33.192 41.651 ;
     RECT  16.08 40.453 18.912 41.891 ;
     RECT  12.528 41.075 13.944 42.035 ;
     RECT  2.4 40.981 2.856 42.179 ;
     RECT  29.184 39.589 29.712 42.227 ;
     RECT  29.28 42.227 29.712 42.275 ;
     RECT  30.72 41.749 30.744 42.419 ;
     RECT  16.08 41.891 16.872 42.517 ;
     RECT  13.056 42.035 13.944 42.803 ;
     RECT  33.072 42.181 33.096 42.803 ;
     RECT  24 41.027 25.272 42.851 ;
     RECT  66.384 2.151 67.512 42.851 ;
     RECT  36.192 41.075 36.216 42.853 ;
     RECT  21.072 41.651 21.096 42.899 ;
     RECT  36.192 42.853 36.456 42.899 ;
     RECT  11.424 40.885 11.448 42.995 ;
     RECT  7.8 41.075 8.112 43.141 ;
     RECT  22.704 42.037 22.728 43.285 ;
     RECT  21.888 43.285 22.728 43.331 ;
     RECT  36.24 42.899 36.456 43.331 ;
     RECT  15.792 42.517 16.872 43.715 ;
     RECT  3.984 41.461 4.2 43.765 ;
     RECT  24 42.851 24.648 43.813 ;
     RECT  25.632 43.765 25.656 43.813 ;
     RECT  34.8 39.923 35.112 43.861 ;
     RECT  15.84 43.715 16.872 44.003 ;
     RECT  9.888 42.949 9.912 44.099 ;
     RECT  3.888 43.765 4.2 44.147 ;
     RECT  11.904 43.285 11.928 44.339 ;
     RECT  28.08 40.547 28.104 44.389 ;
     RECT  34.8 43.861 35.256 44.437 ;
     RECT  14.784 43.861 14.808 44.483 ;
     RECT  17.952 41.891 18.912 44.483 ;
     RECT  13.056 42.803 13.512 44.869 ;
     RECT  18.6 44.483 18.912 44.869 ;
     RECT  20.208 43.285 20.232 44.869 ;
     RECT  15.84 44.003 15.864 45.059 ;
     RECT  18.6 44.869 20.232 45.059 ;
     RECT  27.696 44.389 28.104 45.059 ;
     RECT  7.8 43.141 8.472 45.395 ;
     RECT  34.704 44.437 35.256 45.491 ;
     RECT  23.232 43.813 25.656 45.587 ;
     RECT  10.272 44.437 10.296 45.683 ;
     RECT  5.04 44.773 5.064 45.731 ;
     RECT  12.528 44.869 13.512 45.733 ;
     RECT  2.4 42.179 2.712 45.973 ;
     RECT  11.952 45.733 13.512 46.117 ;
     RECT  10.944 46.117 13.512 46.211 ;
     RECT  12.528 46.211 13.512 46.259 ;
     RECT  13.056 46.259 13.512 46.405 ;
     RECT  36.24 43.331 36.264 46.597 ;
     RECT  37.632 44.965 37.656 46.597 ;
     RECT  36.24 46.597 37.656 46.739 ;
     RECT  29.4 42.275 29.712 46.741 ;
     RECT  10.944 46.211 11.256 46.787 ;
     RECT  23.328 45.587 25.656 46.787 ;
     RECT  30.768 46.549 30.792 46.787 ;
     RECT  24 46.787 25.656 46.789 ;
     RECT  2.4 45.973 2.808 46.835 ;
     RECT  10.944 46.787 10.968 46.885 ;
     RECT  29.28 46.741 29.712 47.027 ;
     RECT  24 46.789 25.752 47.075 ;
     RECT  31.824 46.789 31.848 47.075 ;
     RECT  33.648 44.917 33.672 47.269 ;
     RECT  34.8 45.491 35.256 47.269 ;
     RECT  5.712 47.221 5.736 47.747 ;
     RECT  13.056 46.405 14.088 47.845 ;
     RECT  29.4 47.027 29.712 47.845 ;
     RECT  30.816 47.317 30.84 47.845 ;
     RECT  29.4 47.845 30.84 47.891 ;
     RECT  10.8 46.885 10.968 47.939 ;
     RECT  33.648 47.269 35.256 47.987 ;
     RECT  34.8 47.987 35.256 48.133 ;
     RECT  36.24 46.739 36.792 48.133 ;
     RECT  29.4 47.891 30.696 48.179 ;
     RECT  12.816 47.845 14.088 48.901 ;
     RECT  21.888 43.331 21.912 49.045 ;
     RECT  10.8 47.939 10.824 49.093 ;
     RECT  28.08 45.059 28.104 49.237 ;
     RECT  29.4 48.179 29.712 49.237 ;
     RECT  12.816 48.901 14.232 49.331 ;
     RECT  18.6 45.059 19.656 49.331 ;
     RECT  10.224 49.093 10.92 49.381 ;
     RECT  28.08 49.237 29.712 49.477 ;
     RECT  38.256 48.421 38.28 50.003 ;
     RECT  26.736 47.461 26.76 50.005 ;
     RECT  9.504 49.381 10.92 50.051 ;
     RECT  33.648 47.987 33.672 50.149 ;
     RECT  33.312 50.149 33.672 50.195 ;
     RECT  24 47.075 25.128 50.291 ;
     RECT  12.816 49.331 14.088 50.387 ;
     RECT  16.848 44.003 16.872 50.629 ;
     RECT  18.6 49.331 19.368 50.629 ;
     RECT  3.888 44.147 3.912 50.725 ;
     RECT  3.888 50.725 4.776 50.771 ;
     RECT  26.592 50.005 26.76 50.773 ;
     RECT  28.032 49.477 29.712 50.773 ;
     RECT  33.312 50.195 33.624 50.819 ;
     RECT  26.592 50.773 29.712 50.915 ;
     RECT  21.12 49.045 21.912 50.963 ;
     RECT  39.024 50.245 39.048 50.965 ;
     RECT  40.2 35.939 40.512 50.965 ;
     RECT  7.8 45.395 8.112 51.157 ;
     RECT  34.8 48.133 36.792 51.157 ;
     RECT  16.848 50.629 19.368 51.203 ;
     RECT  24 50.291 25.032 51.253 ;
     RECT  9.504 50.051 10.248 51.587 ;
     RECT  21.12 50.963 21.144 51.635 ;
     RECT  31.392 49.573 31.416 51.635 ;
     RECT  33.6 50.819 33.624 51.781 ;
     RECT  7.392 51.157 8.112 51.829 ;
     RECT  26.592 50.915 26.76 51.877 ;
     RECT  16.848 51.203 19.128 51.923 ;
     RECT  23.904 51.253 25.032 51.923 ;
     RECT  33.168 51.781 33.624 51.923 ;
     RECT  23.904 51.923 24.888 51.971 ;
     RECT  6.816 51.829 8.112 52.021 ;
     RECT  6.576 52.021 8.112 52.067 ;
     RECT  16.848 51.923 19.032 52.403 ;
     RECT  34.8 51.157 36.936 52.403 ;
     RECT  7.68 52.067 8.112 52.405 ;
     RECT  6.576 52.067 6.6 52.451 ;
     RECT  12.816 50.387 13.512 52.453 ;
     RECT  14.544 51.349 14.568 52.453 ;
     RECT  12.816 52.453 14.568 52.499 ;
     RECT  39.024 50.965 40.512 52.499 ;
     RECT  12.816 52.499 14.424 52.883 ;
     RECT  4.752 50.771 4.776 52.885 ;
     RECT  9.504 51.587 9.528 52.981 ;
     RECT  7.68 52.405 8.472 53.027 ;
     RECT  18 52.403 19.032 53.125 ;
     RECT  28.032 50.915 29.712 53.317 ;
     RECT  32.784 53.221 32.808 53.363 ;
     RECT  27.84 53.317 29.712 53.413 ;
     RECT  27.84 53.413 29.832 53.459 ;
     RECT  13.2 52.883 14.424 53.603 ;
     RECT  24 51.971 24.888 53.603 ;
     RECT  18 53.125 19.8 53.987 ;
     RECT  4.512 52.885 4.776 54.131 ;
     RECT  39.024 52.499 39.048 54.133 ;
     RECT  9.504 52.981 9.768 54.179 ;
     RECT  13.2 53.603 14.28 54.179 ;
     RECT  7.8 53.027 8.472 54.371 ;
     RECT  36.24 52.403 36.936 54.373 ;
     RECT  27.936 53.459 29.832 54.613 ;
     RECT  18 53.987 19.032 54.661 ;
     RECT  9.504 54.179 9.528 54.755 ;
     RECT  36.24 54.373 37.128 54.755 ;
     RECT  24 53.603 24.552 55.187 ;
     RECT  38.784 54.133 39.048 55.187 ;
     RECT  27.936 54.613 30.408 55.237 ;
     RECT  38.784 55.187 38.808 55.237 ;
     RECT  27.936 55.237 30.696 55.331 ;
     RECT  7.8 54.371 8.376 55.427 ;
     RECT  24 55.187 24.456 55.669 ;
     RECT  17.664 54.661 19.032 55.715 ;
     RECT  13.2 54.179 13.512 55.765 ;
     RECT  15.792 55.669 15.816 55.811 ;
     RECT  26.208 51.877 26.76 55.813 ;
     RECT  4.752 54.131 4.776 55.907 ;
     RECT  33.6 55.285 33.624 55.907 ;
     RECT  2.4 46.835 2.712 56.341 ;
     RECT  7.8 55.427 8.112 56.677 ;
     RECT  12.768 55.765 13.512 56.677 ;
     RECT  23.856 55.669 24.456 56.677 ;
     RECT  25.68 55.813 26.76 56.723 ;
     RECT  28.08 55.331 30.696 56.723 ;
     RECT  2.4 56.341 2.904 56.965 ;
     RECT  23.184 56.677 24.552 56.965 ;
     RECT  18.6 55.715 19.032 57.059 ;
     RECT  28.08 56.723 30.312 57.059 ;
     RECT  36.24 54.755 37.08 57.301 ;
     RECT  38.16 55.237 38.808 57.301 ;
     RECT  2.304 56.965 2.904 57.347 ;
     RECT  10.656 55.429 10.68 57.635 ;
     RECT  33.504 57.205 33.528 57.685 ;
     RECT  34.8 52.403 35.112 57.685 ;
     RECT  23.184 56.965 24.936 57.731 ;
     RECT  26.208 56.723 26.76 58.115 ;
     RECT  18.6 57.059 18.912 58.117 ;
     RECT  29.232 57.059 30.312 58.309 ;
     RECT  36.24 57.301 38.808 58.355 ;
     RECT  5.088 57.301 5.112 58.403 ;
     RECT  29.184 58.309 30.312 58.645 ;
     RECT  36.24 58.355 38.184 58.739 ;
     RECT  28.08 57.059 28.104 58.931 ;
     RECT  29.184 58.645 30.504 59.171 ;
     RECT  16.08 58.117 16.104 59.173 ;
     RECT  15.552 59.173 16.104 59.219 ;
     RECT  18.6 58.117 19.848 59.221 ;
     RECT  24 57.731 24.936 59.269 ;
     RECT  33.504 57.685 35.112 59.315 ;
     RECT  17.664 59.221 19.848 59.459 ;
     RECT  2.304 57.347 2.856 59.555 ;
     RECT  2.304 59.555 2.808 59.603 ;
     RECT  29.232 59.171 30.504 59.651 ;
     RECT  15.552 59.219 15.576 59.797 ;
     RECT  2.4 59.603 2.808 59.987 ;
     RECT  23.472 59.269 24.936 60.275 ;
     RECT  11.376 59.413 11.4 60.277 ;
     RECT  12.432 56.677 13.512 60.277 ;
     RECT  17.664 59.459 18.912 60.277 ;
     RECT  7.2 56.677 8.112 60.373 ;
     RECT  9.648 59.797 9.672 60.467 ;
     RECT  29.232 59.651 30.264 60.467 ;
     RECT  22.032 59.173 22.056 60.515 ;
     RECT  11.376 60.277 13.512 60.563 ;
     RECT  17.616 60.277 18.912 60.997 ;
     RECT  14.64 59.797 15.576 61.043 ;
     RECT  26.352 58.115 26.76 61.045 ;
     RECT  36.912 58.739 37.8 61.379 ;
     RECT  17.616 60.997 19.032 61.429 ;
     RECT  29.232 60.467 29.712 61.525 ;
     RECT  7.2 60.373 8.616 61.619 ;
     RECT  14.64 61.043 14.664 61.619 ;
     RECT  34.176 59.315 35.112 61.619 ;
     RECT  29.184 61.525 29.712 61.811 ;
     RECT  25.92 61.045 26.76 61.859 ;
     RECT  7.344 61.619 8.616 61.907 ;
     RECT  5.328 61.189 5.352 62.195 ;
     RECT  7.344 61.907 8.112 62.195 ;
     RECT  17.616 61.429 19.368 62.195 ;
     RECT  26.352 61.859 26.76 62.195 ;
     RECT  2.4 59.987 2.712 62.533 ;
     RECT  24 60.275 24.936 62.581 ;
     RECT  10.944 62.197 10.968 62.675 ;
     RECT  2.4 62.533 2.856 62.723 ;
     RECT  23.856 62.581 24.936 62.725 ;
     RECT  21.984 61.909 22.008 62.771 ;
     RECT  23.856 62.725 25.08 63.253 ;
     RECT  23.856 63.253 25.56 64.019 ;
     RECT  2.4 62.723 2.712 64.357 ;
     RECT  2.4 64.357 2.904 64.979 ;
     RECT  20.784 62.341 20.808 65.267 ;
     RECT  5.952 65.221 5.976 65.317 ;
     RECT  24 64.019 25.56 65.507 ;
     RECT  26.592 62.195 26.76 65.603 ;
     RECT  26.592 65.603 26.616 65.651 ;
     RECT  33.408 64.357 33.432 65.653 ;
     RECT  34.8 61.619 35.112 65.653 ;
     RECT  37.776 61.379 37.8 65.987 ;
     RECT  16.704 65.557 16.728 66.131 ;
     RECT  10.32 64.357 10.344 66.133 ;
     RECT  10.32 66.133 10.728 66.179 ;
     RECT  36.336 63.829 36.36 66.179 ;
     RECT  5.952 65.317 6.408 66.181 ;
     RECT  2.4 64.979 2.808 66.227 ;
     RECT  4.848 66.181 6.408 66.227 ;
     RECT  33.408 65.653 35.112 66.901 ;
     RECT  32.448 66.901 35.112 66.947 ;
     RECT  15.264 66.085 15.288 67.235 ;
     RECT  10.704 66.179 10.728 67.237 ;
     RECT  10.704 67.237 10.824 67.283 ;
     RECT  4.848 66.227 5.976 67.331 ;
     RECT  29.232 61.811 29.712 67.331 ;
     RECT  4.848 67.331 5.592 67.571 ;
     RECT  29.28 67.331 29.712 67.667 ;
     RECT  24 65.507 25.08 67.765 ;
     RECT  16.56 67.189 16.584 67.859 ;
     RECT  7.8 62.195 8.112 68.245 ;
     RECT  32.448 66.947 32.472 68.291 ;
     RECT  2.4 66.227 2.712 68.341 ;
     RECT  10.8 67.283 10.824 68.435 ;
     RECT  18.6 62.195 19.368 68.915 ;
     RECT  28.032 66.085 28.056 68.915 ;
     RECT  5.088 67.571 5.592 68.917 ;
     RECT  18.6 68.915 18.912 68.917 ;
     RECT  5.088 68.917 5.736 69.059 ;
     RECT  12.24 60.563 13.512 69.349 ;
     RECT  2.4 68.341 3.144 69.683 ;
     RECT  5.088 69.059 5.592 69.683 ;
     RECT  17.856 68.917 18.912 69.875 ;
     RECT  11.76 69.349 13.512 69.925 ;
     RECT  5.568 69.683 5.592 70.163 ;
     RECT  23.328 67.765 25.08 70.163 ;
     RECT  11.76 69.925 13.608 70.261 ;
     RECT  18.6 69.875 18.912 70.405 ;
     RECT  11.76 70.261 14.232 70.499 ;
     RECT  16.704 69.829 16.728 70.739 ;
     RECT  22.8 70.693 22.824 70.835 ;
     RECT  27.36 69.493 27.384 71.267 ;
     RECT  18.6 70.405 19.896 71.315 ;
     RECT  6.864 68.245 8.112 71.363 ;
     RECT  11.76 70.499 11.784 71.507 ;
     RECT  19.968 71.701 19.992 71.843 ;
     RECT  16.656 70.933 16.68 72.371 ;
     RECT  11.952 71.797 11.976 72.419 ;
     RECT  24 70.163 25.08 72.419 ;
     RECT  24 72.419 24.408 74.147 ;
     RECT  10.272 73.477 10.296 74.339 ;
     RECT  15.984 72.901 16.008 74.341 ;
     RECT  15.408 74.341 16.008 74.675 ;
     RECT  12 73.381 12.024 75.011 ;
     RECT  13.2 70.499 14.232 75.155 ;
     RECT  15.408 74.675 15.432 75.251 ;
     RECT  59.04 55.813 59.064 81.539 ;
     RECT  34.176 66.947 35.112 82.259 ;
     RECT  2.4 69.683 2.712 84.249 ;
     RECT  7.8 71.363 8.112 84.249 ;
     RECT  13.2 75.155 13.512 84.249 ;
     RECT  18.6 71.315 18.912 84.249 ;
     RECT  24 74.147 24.312 84.249 ;
     RECT  29.4 67.667 29.712 84.249 ;
     RECT  34.8 82.259 35.112 84.249 ;
     RECT  40.2 52.499 40.512 84.249 ;
     RECT  45.6 2.151 45.912 84.249 ;
     RECT  51 2.151 51.312 84.249 ;
     RECT  56.4 2.151 56.712 84.249 ;
     RECT  61.8 2.151 62.112 84.249 ;
     RECT  67.2 42.851 67.512 84.249 ;
     RECT  72.6 2.151 72.912 84.249 ;
     RECT  78 2.151 78.312 84.249 ;
     RECT  83.4 2.151 83.712 84.249 ;
     RECT  2.4 84.249 2.52 84.263 ;
     RECT  7.8 84.249 7.92 84.263 ;
     RECT  13.2 84.249 13.32 84.263 ;
     RECT  18.6 84.249 18.72 84.263 ;
     RECT  24 84.249 24.12 84.263 ;
     RECT  29.4 84.249 29.52 84.263 ;
     RECT  34.8 84.249 34.92 84.263 ;
     RECT  40.2 84.249 40.32 84.263 ;
     RECT  45.6 84.249 45.72 84.263 ;
     RECT  51 84.249 51.12 84.263 ;
     RECT  56.4 84.249 56.52 84.263 ;
     RECT  61.8 84.249 61.92 84.263 ;
     RECT  67.2 84.249 67.32 84.263 ;
     RECT  72.6 84.249 72.72 84.263 ;
     RECT  78 84.249 78.12 84.263 ;
     RECT  83.4 84.249 83.52 84.263 ;
     RECT  58.992 84.325 59.496 85.477 ;
     RECT  58.896 85.477 59.496 86.245 ;
     RECT  58.8 86.245 59.496 86.352 ;
     RECT  24.312 3.829 25.776 12.517 ;
     RECT  18.912 8.437 20.208 9.971 ;
     RECT  11.88 9.637 13.2 9.971 ;
     RECT  18.912 9.971 19.512 10.789 ;
     RECT  11.424 11.171 11.448 11.365 ;
     RECT  11.16 11.365 11.448 11.941 ;
     RECT  11.16 11.941 12.528 12.995 ;
     RECT  24.312 12.517 25.44 13.619 ;
     RECT  11.16 12.995 13.2 14.485 ;
     RECT  13.512 13.093 14.976 13.235 ;
     RECT  13.512 13.235 15.216 13.573 ;
     RECT  13.704 13.573 15.216 14.243 ;
     RECT  24.312 13.619 25.8 13.621 ;
     RECT  24.456 13.621 25.8 13.813 ;
     RECT  24.984 13.813 25.8 13.909 ;
     RECT  24.984 13.909 26.4 15.011 ;
     RECT  11.688 14.485 13.2 15.443 ;
     RECT  18.912 14.963 19.512 15.205 ;
     RECT  24.984 15.011 25.032 16.501 ;
     RECT  18.912 15.205 20.496 16.405 ;
     RECT  8.376 15.301 9.648 15.443 ;
     RECT  9.672 15.301 10.992 15.443 ;
     RECT  16.296 15.829 17.76 17.171 ;
     RECT  14.232 16.405 15.648 17.651 ;
     RECT  18.912 16.405 20.304 19.285 ;
     RECT  8.328 16.595 8.376 17.171 ;
     RECT  8.112 17.171 8.376 17.941 ;
     RECT  8.112 17.941 9.12 20.437 ;
     RECT  13.512 18.803 13.608 20.101 ;
     RECT  18.24 18.851 18.6 20.053 ;
     RECT  31.728 18.851 31.824 19.813 ;
     RECT  18.912 19.285 19.968 20.387 ;
     RECT  7.344 20.147 7.68 21.493 ;
     RECT  22.776 20.723 24 24.563 ;
     RECT  8.112 22.643 9.12 22.835 ;
     RECT  13.656 22.789 14.784 23.029 ;
     RECT  13.608 23.267 14.784 23.363 ;
     RECT  13.608 23.363 14.928 24.947 ;
     RECT  21.672 23.651 22.752 24.131 ;
     RECT  3.528 24.325 4.56 24.469 ;
     RECT  22.752 24.563 24 25.861 ;
     RECT  19.704 24.853 21.024 25.043 ;
     RECT  19.704 25.043 20.76 26.149 ;
     RECT  29.832 25.381 30.816 25.523 ;
     RECT  16.488 25.429 17.952 25.475 ;
     RECT  16.488 25.475 18.336 26.677 ;
     RECT  22.776 25.861 24 26.819 ;
     RECT  35.256 25.955 35.304 26.725 ;
     RECT  19.704 26.149 20.736 27.299 ;
     RECT  17.304 26.677 18.336 27.059 ;
     RECT  33.672 26.725 34.8 28.451 ;
     RECT  35.256 26.725 36.48 26.915 ;
     RECT  35.208 26.915 36.48 27.971 ;
     RECT  2.712 27.059 3.696 28.643 ;
     RECT  17.304 27.059 18.432 27.971 ;
     RECT  30.456 27.157 31.536 29.171 ;
     RECT  7.488 27.827 7.68 27.829 ;
     RECT  6.264 27.829 7.68 29.029 ;
     RECT  10.776 27.877 11.952 29.125 ;
     RECT  11.976 27.877 13.056 30.421 ;
     RECT  35.208 27.971 35.256 28.741 ;
     RECT  4.632 28.115 6.24 29.413 ;
     RECT  34.272 28.451 34.8 29.029 ;
     RECT  6.264 29.029 7.44 29.699 ;
     RECT  30.264 29.171 31.536 31.139 ;
     RECT  10.776 29.411 11.952 30.275 ;
     RECT  4.728 29.413 6.24 29.699 ;
     RECT  31.56 29.699 33.072 31.333 ;
     RECT  18.432 29.795 18.48 30.997 ;
     RECT  10.584 30.275 11.952 30.803 ;
     RECT  35.208 30.467 35.256 31.237 ;
     RECT  16.584 30.997 17.952 31.427 ;
     RECT  29.928 31.139 31.536 32.485 ;
     RECT  33.096 31.141 34.368 32.339 ;
     RECT  35.208 31.237 36.384 32.483 ;
     RECT  6.312 31.285 7.44 31.955 ;
     RECT  6.312 31.955 7.68 32.339 ;
     RECT  35.208 32.483 36.312 33.061 ;
     RECT  30.216 32.485 31.536 34.259 ;
     RECT  35.304 33.061 36.312 33.589 ;
     RECT  10.56 33.155 10.584 34.117 ;
     RECT  35.304 33.589 36.288 34.931 ;
     RECT  5.4 34.355 5.688 35.077 ;
     RECT  7.392 34.451 7.68 35.077 ;
     RECT  25.08 34.501 26.256 35.171 ;
     RECT  2.712 34.645 3.984 35.893 ;
     RECT  4.008 34.645 5.376 35.651 ;
     RECT  35.304 34.931 36.312 35.413 ;
     RECT  26.664 35.029 28.08 37.091 ;
     RECT  28.104 35.029 29.088 36.325 ;
     RECT  5.4 35.077 6.672 35.651 ;
     RECT  6.696 35.077 7.68 35.845 ;
     RECT  31.56 35.317 33.024 36.229 ;
     RECT  35.928 35.413 36.312 35.893 ;
     RECT  29.712 35.795 29.928 35.845 ;
     RECT  29.712 35.845 30.816 37.715 ;
     RECT  35.928 35.893 37.296 36.325 ;
     RECT  31.896 36.229 33.024 36.371 ;
     RECT  30.84 36.275 31.872 36.371 ;
     RECT  36.216 36.325 37.296 37.283 ;
     RECT  28.104 36.515 29.232 37.573 ;
     RECT  6.672 36.803 6.72 37.573 ;
     RECT  19.704 37.091 19.944 38.581 ;
     RECT  27.696 37.091 28.08 38.149 ;
     RECT  5.448 37.573 6.72 37.619 ;
     RECT  28.104 37.573 29.184 37.763 ;
     RECT  35.112 37.619 36.192 42.899 ;
     RECT  29.712 37.715 30.84 38.533 ;
     RECT  28.104 37.763 29.28 39.589 ;
     RECT  39.192 38.101 40.2 39.395 ;
     RECT  29.712 38.533 30.864 41.075 ;
     RECT  19.704 38.581 20.688 39.875 ;
     RECT  20.712 38.581 21.744 39.395 ;
     RECT  13.512 38.773 14.544 39.781 ;
     RECT  14.568 38.773 15.936 38.867 ;
     RECT  14.568 38.867 16.08 39.827 ;
     RECT  10.512 39.539 10.536 39.877 ;
     RECT  28.104 39.589 29.184 42.227 ;
     RECT  18.912 39.875 20.688 40.165 ;
     RECT  10.2 39.877 10.536 40.885 ;
     RECT  16.872 39.877 18 40.453 ;
     RECT  18.912 40.165 19.968 41.651 ;
     RECT  2.808 40.741 3.984 40.981 ;
     RECT  10.2 40.885 11.424 41.651 ;
     RECT  11.448 40.885 12.528 42.035 ;
     RECT  2.856 40.981 3.984 42.179 ;
     RECT  23.904 41.027 24 42.037 ;
     RECT  29.712 41.075 30.744 41.749 ;
     RECT  10.176 41.651 11.424 42.949 ;
     RECT  29.712 41.749 30.72 42.419 ;
     RECT  16.872 41.891 17.952 44.483 ;
     RECT  11.448 42.035 13.056 42.995 ;
     RECT  22.728 42.037 24 43.331 ;
     RECT  2.712 42.179 3.984 43.765 ;
     RECT  28.104 42.227 29.28 42.275 ;
     RECT  28.104 42.275 29.4 46.741 ;
     RECT  13.512 42.803 13.944 43.861 ;
     RECT  24.648 42.851 25.272 43.765 ;
     RECT  35.112 42.899 36.24 43.861 ;
     RECT  9.912 42.949 11.424 42.995 ;
     RECT  9.912 42.995 10.296 44.099 ;
     RECT  11.904 42.995 13.056 43.285 ;
     RECT  8.472 43.141 9.888 44.099 ;
     RECT  11.928 43.285 13.056 44.339 ;
     RECT  18.912 43.285 20.208 44.869 ;
     RECT  21.912 43.331 24 43.813 ;
     RECT  15.792 43.715 15.84 43.861 ;
     RECT  2.712 43.765 3.888 45.973 ;
     RECT  24.648 43.765 25.632 43.813 ;
     RECT  21.912 43.813 23.232 45.587 ;
     RECT  13.512 43.861 14.784 44.483 ;
     RECT  14.808 43.861 15.84 44.483 ;
     RECT  35.256 43.861 36.24 48.133 ;
     RECT  15.864 44.003 16.848 45.059 ;
     RECT  10.272 44.099 10.296 44.437 ;
     RECT  3.912 44.147 4.2 44.773 ;
     RECT  11.952 44.339 13.056 44.869 ;
     RECT  3.912 44.773 5.04 45.731 ;
     RECT  11.952 44.869 12.528 45.733 ;
     RECT  33.672 44.917 34.704 45.491 ;
     RECT  36.264 44.965 37.632 46.597 ;
     RECT  33.672 45.491 34.8 47.269 ;
     RECT  21.912 45.587 23.328 46.787 ;
     RECT  2.808 45.973 3.888 46.835 ;
     RECT  11.256 46.211 12.528 46.259 ;
     RECT  29.712 46.549 30.768 46.787 ;
     RECT  28.104 46.741 29.28 47.027 ;
     RECT  29.712 46.787 30.792 46.789 ;
     RECT  29.712 46.789 31.824 47.075 ;
     RECT  2.712 46.835 3.888 50.771 ;
     RECT  28.104 47.027 29.4 49.237 ;
     RECT  29.712 47.075 30.84 47.317 ;
     RECT  29.712 47.317 30.816 47.845 ;
     RECT  26.76 47.461 28.08 49.477 ;
     RECT  10.824 47.939 10.92 49.093 ;
     RECT  33.672 47.987 34.8 50.195 ;
     RECT  36.792 48.421 38.256 50.003 ;
     RECT  19.656 49.045 21.12 49.331 ;
     RECT  8.112 49.381 9.504 52.405 ;
     RECT  26.76 49.477 28.032 50.773 ;
     RECT  36.792 50.003 36.936 51.157 ;
     RECT  25.128 50.005 26.592 50.291 ;
     RECT  33.624 50.195 34.8 51.923 ;
     RECT  39.048 50.245 40.2 50.965 ;
     RECT  13.512 50.387 14.088 51.349 ;
     RECT  33.312 50.819 33.6 51.781 ;
     RECT  26.76 50.915 28.032 53.317 ;
     RECT  13.512 51.349 14.544 52.453 ;
     RECT  9.528 51.587 9.768 52.981 ;
     RECT  25.032 51.877 26.208 51.923 ;
     RECT  19.032 51.923 19.128 53.125 ;
     RECT  24.888 51.923 26.208 53.603 ;
     RECT  6.6 52.067 7.68 52.451 ;
     RECT  35.112 52.403 36.24 58.739 ;
     RECT  8.472 52.405 9.504 54.371 ;
     RECT  39.048 52.499 40.2 55.187 ;
     RECT  26.76 53.317 27.84 53.459 ;
     RECT  26.76 53.459 27.936 55.331 ;
     RECT  8.376 54.371 9.504 54.755 ;
     RECT  37.08 54.755 37.128 55.237 ;
     RECT  24.456 55.187 24.552 55.813 ;
     RECT  38.808 55.187 40.2 58.355 ;
     RECT  37.08 55.237 38.16 57.301 ;
     RECT  33.624 55.285 34.8 55.907 ;
     RECT  26.76 55.331 28.08 58.931 ;
     RECT  24.456 55.813 25.68 56.677 ;
     RECT  33.6 55.907 34.8 57.205 ;
     RECT  24.552 56.677 25.68 56.723 ;
     RECT  24.552 56.723 26.208 56.965 ;
     RECT  24.936 56.965 26.208 58.115 ;
     RECT  18.912 57.059 19.032 58.117 ;
     RECT  28.104 57.059 29.232 58.309 ;
     RECT  33.528 57.205 34.8 57.685 ;
     RECT  24.936 58.115 26.352 61.045 ;
     RECT  28.104 58.309 29.184 58.931 ;
     RECT  22.056 59.269 23.472 60.275 ;
     RECT  11.4 59.413 12.432 60.277 ;
     RECT  13.512 59.797 14.64 61.619 ;
     RECT  8.616 60.373 9.648 60.467 ;
     RECT  24.936 61.045 25.92 61.859 ;
     RECT  24.936 61.859 26.352 62.195 ;
     RECT  24.936 62.195 26.592 62.725 ;
     RECT  10.968 62.197 12.24 62.675 ;
     RECT  19.368 62.341 20.784 65.267 ;
     RECT  20.808 62.341 21.984 62.771 ;
     RECT  25.08 62.725 26.592 63.253 ;
     RECT  25.56 63.253 26.592 65.507 ;
     RECT  35.112 63.829 36.336 66.179 ;
     RECT  36.36 63.829 37.776 65.987 ;
     RECT  33.432 64.357 34.8 65.653 ;
     RECT  6.408 65.317 7.8 66.227 ;
     RECT  25.08 65.507 26.592 65.651 ;
     RECT  15.288 66.085 16.704 66.131 ;
     RECT  28.056 66.085 29.232 67.331 ;
     RECT  15.288 66.131 16.584 67.189 ;
     RECT  10.728 66.133 12.24 67.237 ;
     RECT  15.288 67.189 16.56 67.235 ;
     RECT  10.824 67.237 12.24 68.435 ;
     RECT  5.592 67.331 5.976 68.245 ;
     RECT  28.056 67.331 29.28 67.667 ;
     RECT  28.056 67.667 29.4 68.915 ;
     RECT  5.592 68.245 6.864 68.917 ;
     RECT  11.76 68.435 12.24 69.349 ;
     RECT  18.912 68.915 19.368 70.405 ;
     RECT  5.736 68.917 6.864 69.059 ;
     RECT  5.592 69.059 6.864 70.163 ;
     RECT  16.728 69.829 17.856 69.875 ;
     RECT  23.328 70.163 24 70.693 ;
     RECT  11.784 70.499 13.2 71.507 ;
     RECT  22.824 70.693 24 70.835 ;
     RECT  18.912 71.315 19.896 71.701 ;
     RECT  11.952 71.507 13.2 71.797 ;
     RECT  18.912 71.701 19.968 71.843 ;
     RECT  11.976 71.797 13.2 72.419 ;
     RECT  12 72.419 13.2 73.381 ;
     RECT  12.024 73.381 13.2 75.011 ;
     RECT  14.232 74.341 15.408 75.155 ;
  END
END ot_hgi_qdq_wr_fin
END LIBRARY
